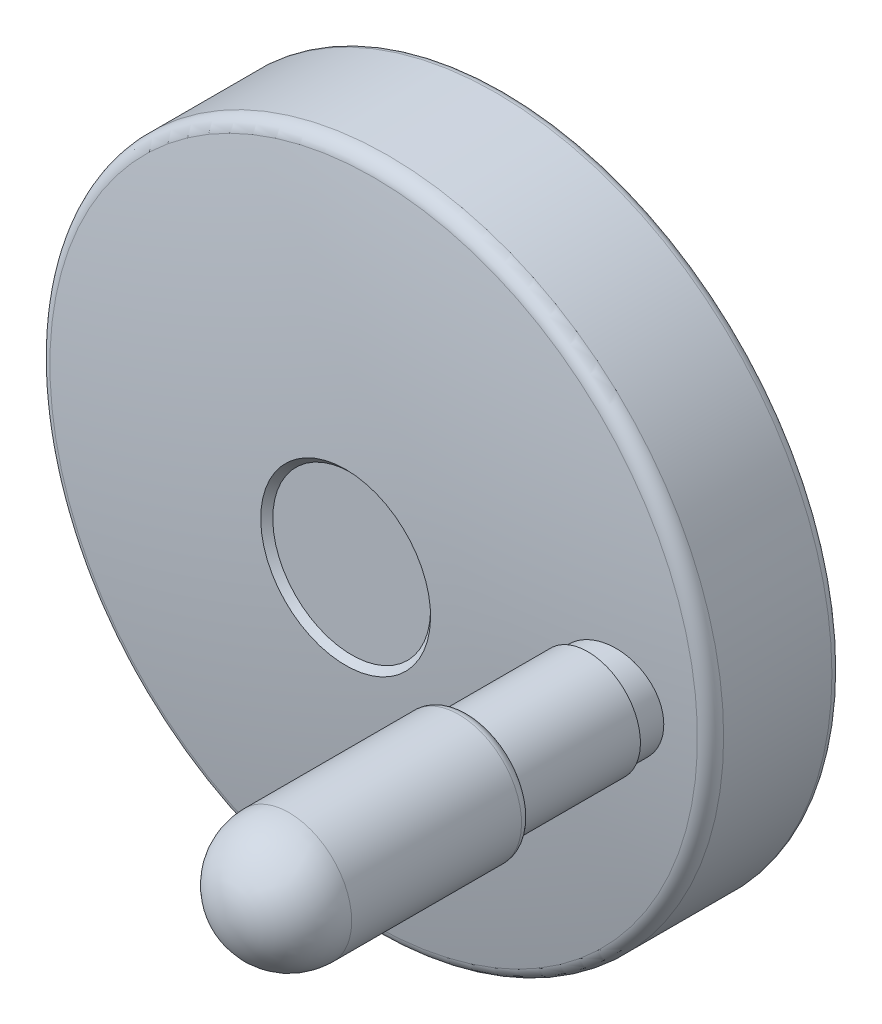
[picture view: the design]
ISO-10303-21;
HEADER;
FILE_DESCRIPTION(('STEP AP214'),'2;1');
FILE_NAME('part.step','',(''),(''),'','','');
FILE_SCHEMA(('AUTOMOTIVE_DESIGN { 1 0 10303 214 1 1 1 1 }'));
ENDSEC;
DATA;
#1=APPLICATION_CONTEXT('core data for automotive mechanical design processes');
#2=APPLICATION_PROTOCOL_DEFINITION('international standard','automotive_design',2000,#1);
#3=PRODUCT_CONTEXT('',#1,'mechanical');
#4=PRODUCT('Part','Part','',(#3));
#5=PRODUCT_RELATED_PRODUCT_CATEGORY('part','',(#4));
#6=PRODUCT_DEFINITION_FORMATION('','',#4);
#7=PRODUCT_DEFINITION_CONTEXT('part definition',#1,'design');
#8=PRODUCT_DEFINITION('design','',#6,#7);
#9=PRODUCT_DEFINITION_SHAPE('','',#8);
#10=(LENGTH_UNIT() NAMED_UNIT(*) SI_UNIT(.MILLI.,.METRE.));
#11=(NAMED_UNIT(*) PLANE_ANGLE_UNIT() SI_UNIT($,.RADIAN.));
#12=(NAMED_UNIT(*) SI_UNIT($,.STERADIAN.) SOLID_ANGLE_UNIT());
#13=UNCERTAINTY_MEASURE_WITH_UNIT(LENGTH_MEASURE(1.E-05),#10,'distance_accuracy_value','');
#14=(GEOMETRIC_REPRESENTATION_CONTEXT(3) GLOBAL_UNCERTAINTY_ASSIGNED_CONTEXT((#13)) GLOBAL_UNIT_ASSIGNED_CONTEXT((#10,
#11,#12)) REPRESENTATION_CONTEXT('',''));
#15=CARTESIAN_POINT('',(0.,0.,0.));
#16=DIRECTION('',(0.,0.,1.));
#17=DIRECTION('',(1.,0.,0.));
#18=AXIS2_PLACEMENT_3D('',#15,#16,#17);
#19=CARTESIAN_POINT('',(0.,0.,29.));
#20=DIRECTION('',(0.,0.,1.));
#21=DIRECTION('',(0.,1.,0.));
#22=AXIS2_PLACEMENT_3D('',#19,#20,#21);
#23=PLANE('',#22);
#24=CARTESIAN_POINT('',(30.5,0.,29.));
#25=DIRECTION('',(0.,0.,1.));
#26=DIRECTION('',(0.,1.,0.));
#27=AXIS2_PLACEMENT_3D('',#24,#25,#26);
#28=CIRCLE('',#27,4.875);
#29=CARTESIAN_POINT('',(30.5,4.87499999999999,29.));
#30=VERTEX_POINT('',#29);
#31=EDGE_CURVE('E297',#30,#30,#28,.T.);
#32=ORIENTED_EDGE('',*,*,#31,.F.);
#33=EDGE_LOOP('',(#32));
#34=FACE_BOUND('',#33,.T.);
#35=CARTESIAN_POINT('',(30.5,0.,29.));
#36=DIRECTION('',(0.,0.,-1.));
#37=DIRECTION('',(0.,-1.,0.));
#38=AXIS2_PLACEMENT_3D('',#35,#36,#37);
#39=CIRCLE('',#38,6.);
#40=CARTESIAN_POINT('',(30.5,-6.,29.));
#41=VERTEX_POINT('',#40);
#42=EDGE_CURVE('E768',#41,#41,#39,.T.);
#43=ORIENTED_EDGE('',*,*,#42,.F.);
#44=EDGE_LOOP('',(#43));
#45=FACE_BOUND('',#44,.T.);
#46=ADVANCED_FACE('F15',(#34,#45),#23,.T.);
#47=CARTESIAN_POINT('',(30.5,0.,25.));
#48=DIRECTION('',(0.,0.,-1.));
#49=DIRECTION('',(0.,-1.,0.));
#50=AXIS2_PLACEMENT_3D('',#47,#48,#49);
#51=CYLINDRICAL_SURFACE('',#50,6.);
#52=CARTESIAN_POINT('',(24.5,0.,27.6143071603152));
#53=CARTESIAN_POINT('',(24.5000009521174,0.167229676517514,27.6143070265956));
#54=CARTESIAN_POINT('',(24.5069975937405,0.334490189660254,27.6133186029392));
#55=CARTESIAN_POINT('',(24.5349379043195,0.66785375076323,27.6093713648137));
#56=CARTESIAN_POINT('',(24.5558858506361,0.833956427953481,27.606411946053));
#57=CARTESIAN_POINT('',(24.6116186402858,1.16405510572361,27.5985380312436));
#58=CARTESIAN_POINT('',(24.6464255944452,1.3280473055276,27.5936204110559));
#59=CARTESIAN_POINT('',(24.7296467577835,1.65260800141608,27.5818621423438));
#60=CARTESIAN_POINT('',(24.7780716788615,1.81317369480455,27.5750199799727));
#61=CARTESIAN_POINT('',(24.8880461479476,2.12930204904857,27.5594802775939));
#62=CARTESIAN_POINT('',(24.9495700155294,2.28487382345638,27.5507863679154));
#63=CARTESIAN_POINT('',(25.0853707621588,2.59031604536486,27.5315950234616));
#64=CARTESIAN_POINT('',(25.1596533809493,2.74018388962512,27.5210967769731));
#65=CARTESIAN_POINT('',(25.3204096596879,3.0331103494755,27.4983754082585));
#66=CARTESIAN_POINT('',(25.4068843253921,3.17616840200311,27.4861521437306));
#67=CARTESIAN_POINT('',(25.591344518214,3.45441028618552,27.4600760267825));
#68=CARTESIAN_POINT('',(25.6893249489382,3.58959756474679,27.4462238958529));
#69=CARTESIAN_POINT('',(25.8966280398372,3.85188881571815,27.4169129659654));
#70=CARTESIAN_POINT('',(26.0060044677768,3.97894944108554,27.4014465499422));
#71=CARTESIAN_POINT('',(26.2347880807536,4.22326275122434,27.3690915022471));
#72=CARTESIAN_POINT('',(26.3541854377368,4.34052482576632,27.3522042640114));
#73=CARTESIAN_POINT('',(26.6023049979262,4.56463962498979,27.3171064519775));
#74=CARTESIAN_POINT('',(26.7310317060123,4.67148726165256,27.2988952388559));
#75=CARTESIAN_POINT('',(26.9968731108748,4.87401595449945,27.2612810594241));
#76=CARTESIAN_POINT('',(27.1339898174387,4.96969431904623,27.2418778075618));
#77=CARTESIAN_POINT('',(27.4168805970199,5.15002553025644,27.2018404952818));
#78=CARTESIAN_POINT('',(27.5627213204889,5.2345717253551,27.1811969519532));
#79=CARTESIAN_POINT('',(27.8609443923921,5.39108100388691,27.1389775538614));
#80=CARTESIAN_POINT('',(28.0133291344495,5.46303943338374,27.1174013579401));
#81=CARTESIAN_POINT('',(28.3234609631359,5.59383505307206,27.0734828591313));
#82=CARTESIAN_POINT('',(28.4812062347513,5.65267663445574,27.051140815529));
#83=CARTESIAN_POINT('',(28.8010597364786,5.75690064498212,27.0058315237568));
#84=CARTESIAN_POINT('',(28.9631695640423,5.80227807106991,26.9828640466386));
#85=CARTESIAN_POINT('',(29.291955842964,5.8795739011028,26.9362744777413));
#86=CARTESIAN_POINT('',(29.4586593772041,5.91137478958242,26.9126484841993));
#87=CARTESIAN_POINT('',(29.7941802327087,5.96075351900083,26.865088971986));
#88=CARTESIAN_POINT('',(29.9629983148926,5.97832608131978,26.8411553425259));
#89=CARTESIAN_POINT('',(30.3014406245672,5.99910895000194,26.7931657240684));
#90=CARTESIAN_POINT('',(30.4710645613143,6.002324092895,26.7691097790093));
#91=CARTESIAN_POINT('',(30.8100436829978,5.9943828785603,26.7210279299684));
#92=CARTESIAN_POINT('',(30.9793987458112,5.98322122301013,26.6970020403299));
#93=CARTESIAN_POINT('',(31.3172944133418,5.94651420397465,26.6490578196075));
#94=CARTESIAN_POINT('',(31.4858285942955,5.92090852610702,26.6251403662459));
#95=CARTESIAN_POINT('',(31.8202181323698,5.8554299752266,26.5776778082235));
#96=CARTESIAN_POINT('',(31.9860725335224,5.8155521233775,26.5541328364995));
#97=CARTESIAN_POINT('',(32.3138307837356,5.72180624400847,26.5075962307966));
#98=CARTESIAN_POINT('',(32.4757352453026,5.66794040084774,26.4846045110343));
#99=CARTESIAN_POINT('',(32.7944560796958,5.54657992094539,26.4393365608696));
#100=CARTESIAN_POINT('',(32.9512724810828,5.47908536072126,26.4170603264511));
#101=CARTESIAN_POINT('',(33.2584436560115,5.33104219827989,26.3734192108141));
#102=CARTESIAN_POINT('',(33.4088081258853,5.25051411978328,26.3520529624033));
#103=CARTESIAN_POINT('',(33.7021894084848,5.07691097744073,26.3103586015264));
#104=CARTESIAN_POINT('',(33.8452088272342,4.98384040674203,26.2900301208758));
#105=CARTESIAN_POINT('',(34.1229453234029,4.7857464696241,26.2505479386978));
#106=CARTESIAN_POINT('',(34.2576602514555,4.680720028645,26.2313945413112));
#107=CARTESIAN_POINT('',(34.5177008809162,4.45950749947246,26.1944180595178));
#108=CARTESIAN_POINT('',(34.6430301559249,4.34332569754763,26.176594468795));
#109=CARTESIAN_POINT('',(34.8825480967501,4.10146660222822,26.1425277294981));
#110=CARTESIAN_POINT('',(34.9968109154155,3.97586422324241,26.1262740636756));
#111=CARTESIAN_POINT('',(35.2143248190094,3.71536314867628,26.0953299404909));
#112=CARTESIAN_POINT('',(35.3175801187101,3.58046804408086,26.0806388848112));
#113=CARTESIAN_POINT('',(35.5124335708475,3.3021790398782,26.0529128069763));
#114=CARTESIAN_POINT('',(35.6040221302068,3.15877828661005,26.0398791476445));
#115=CARTESIAN_POINT('',(35.7747155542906,2.86465960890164,26.0155864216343));
#116=CARTESIAN_POINT('',(35.8538252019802,2.71394451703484,26.004326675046));
#117=CARTESIAN_POINT('',(35.998374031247,2.40755662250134,25.9837515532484));
#118=CARTESIAN_POINT('',(36.0639247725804,2.25193750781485,25.9744203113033));
#119=CARTESIAN_POINT('',(36.18168352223,1.93569835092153,25.957656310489));
#120=CARTESIAN_POINT('',(36.2338967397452,1.77508028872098,25.9502228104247));
#121=CARTESIAN_POINT('',(36.3245353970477,1.45023312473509,25.9373182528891));
#122=CARTESIAN_POINT('',(36.3629849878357,1.28601089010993,25.9318437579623));
#123=CARTESIAN_POINT('',(36.4259166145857,0.954926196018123,25.9228832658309));
#124=CARTESIAN_POINT('',(36.4504056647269,0.788065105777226,25.9193962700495));
#125=CARTESIAN_POINT('',(36.4785444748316,0.517442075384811,25.9153895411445));
#126=CARTESIAN_POINT('',(36.4865876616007,0.414126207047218,25.9142442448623));
#127=CARTESIAN_POINT('',(36.4973157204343,0.207210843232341,25.9127166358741));
#128=CARTESIAN_POINT('',(36.5000005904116,0.103611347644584,25.9123343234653));
#129=CARTESIAN_POINT('',(36.4999990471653,-0.167212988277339,25.9123345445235));
#130=CARTESIAN_POINT('',(36.4930037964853,-0.334456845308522,25.9133306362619));
#131=CARTESIAN_POINT('',(36.4650690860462,-0.667787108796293,25.9173083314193));
#132=CARTESIAN_POINT('',(36.4441253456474,-0.833873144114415,25.9202905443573));
#133=CARTESIAN_POINT('',(36.3884038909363,-1.16393864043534,25.9282245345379));
#134=CARTESIAN_POINT('',(36.3536040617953,-1.32791429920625,25.933179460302));
#135=CARTESIAN_POINT('',(36.2704002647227,-1.65244196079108,25.9450257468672));
#136=CARTESIAN_POINT('',(36.221985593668,-1.81299116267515,25.9519186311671));
#137=CARTESIAN_POINT('',(36.1120351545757,-2.12908618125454,25.9675715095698));
#138=CARTESIAN_POINT('',(36.0505251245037,-2.28464113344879,25.9763278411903));
#139=CARTESIAN_POINT('',(35.9147556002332,-2.59005051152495,25.9956540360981));
#140=CARTESIAN_POINT('',(35.8404903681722,-2.73990233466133,26.0062247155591));
#141=CARTESIAN_POINT('',(35.6797723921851,-3.03279819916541,26.0290988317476));
#142=CARTESIAN_POINT('',(35.5933186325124,-3.17584167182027,26.0414024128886));
#143=CARTESIAN_POINT('',(35.4089037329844,-3.45405634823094,26.0676446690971));
#144=CARTESIAN_POINT('',(35.3109476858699,-3.58923099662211,26.0815826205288));
#145=CARTESIAN_POINT('',(35.1036876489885,-3.85151105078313,26.111069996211));
#146=CARTESIAN_POINT('',(34.9943289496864,-3.97857235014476,26.1266271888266));
#147=CARTESIAN_POINT('',(34.7655819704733,-4.22288853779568,26.159164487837));
#148=CARTESIAN_POINT('',(34.6462035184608,-4.34015281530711,26.1761431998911));
#149=CARTESIAN_POINT('',(34.398122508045,-4.56427410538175,26.211422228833));
#150=CARTESIAN_POINT('',(34.2694154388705,-4.67112602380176,26.2297231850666));
#151=CARTESIAN_POINT('',(34.0036135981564,-4.87366567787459,26.2675125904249));
#152=CARTESIAN_POINT('',(33.8665168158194,-4.96935072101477,26.2870013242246));
#153=CARTESIAN_POINT('',(33.5836468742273,-5.14971003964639,26.3272063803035));
#154=CARTESIAN_POINT('',(33.4378060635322,-5.23427609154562,26.3479322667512));
#155=CARTESIAN_POINT('',(33.1395801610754,-5.39082451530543,26.3903076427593));
#156=CARTESIAN_POINT('',(32.9871926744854,-5.46280223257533,26.4119574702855));
#157=CARTESIAN_POINT('',(32.6770523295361,-5.59363564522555,26.4560124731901));
#158=CARTESIAN_POINT('',(32.5193012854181,-5.65249572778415,26.4784173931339));
#159=CARTESIAN_POINT('',(32.1994329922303,-5.75675557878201,26.5238400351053));
#160=CARTESIAN_POINT('',(32.037314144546,-5.80215034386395,26.546857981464));
#161=CARTESIAN_POINT('',(31.7085023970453,-5.87948025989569,26.5935356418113));
#162=CARTESIAN_POINT('',(31.5417823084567,-5.91129754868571,26.6171991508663));
#163=CARTESIAN_POINT('',(31.2062247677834,-5.96070612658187,26.6648187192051));
#164=CARTESIAN_POINT('',(31.0373865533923,-5.97829213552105,26.6887748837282));
#165=CARTESIAN_POINT('',(30.6989007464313,-5.99909827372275,26.7367939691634));
#166=CARTESIAN_POINT('',(30.5292534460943,-6.00232324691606,26.7608568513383));
#167=CARTESIAN_POINT('',(30.1902247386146,-5.99439745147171,26.8089368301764));
#168=CARTESIAN_POINT('',(30.0208434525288,-5.98324138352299,26.832953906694));
#169=CARTESIAN_POINT('',(29.6829113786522,-5.94654272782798,26.8808623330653));
#170=CARTESIAN_POINT('',(29.5143668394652,-5.92094136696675,26.9047527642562));
#171=CARTESIAN_POINT('',(29.1799545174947,-5.85546920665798,26.9521464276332));
#172=CARTESIAN_POINT('',(29.0140876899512,-5.81559342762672,26.9756495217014));
#173=CARTESIAN_POINT('',(28.6863032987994,-5.72184911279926,27.0220886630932));
#174=CARTESIAN_POINT('',(28.5243851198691,-5.66798277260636,27.0450247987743));
#175=CARTESIAN_POINT('',(28.2056361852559,-5.54661851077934,27.0901694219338));
#176=CARTESIAN_POINT('',(28.0488054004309,-5.47912066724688,27.1123779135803));
#177=CARTESIAN_POINT('',(27.7416272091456,-5.33107857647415,27.1558703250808));
#178=CARTESIAN_POINT('',(27.5912692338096,-5.25055670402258,27.1771557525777));
#179=CARTESIAN_POINT('',(27.2978996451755,-5.07696686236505,27.2186807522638));
#180=CARTESIAN_POINT('',(27.1548854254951,-4.98390338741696,27.2389206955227));
#181=CARTESIAN_POINT('',(26.877158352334,-4.78582465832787,27.2782205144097));
#182=CARTESIAN_POINT('',(26.7424476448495,-4.68080633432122,27.297280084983));
#183=CARTESIAN_POINT('',(26.4824145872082,-4.45961119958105,27.3340663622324));
#184=CARTESIAN_POINT('',(26.3570886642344,-4.343438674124,27.3517935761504));
#185=CARTESIAN_POINT('',(26.1175812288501,-4.10160413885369,27.3856677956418));
#186=CARTESIAN_POINT('',(26.0033251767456,-3.97601742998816,27.4018253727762));
#187=CARTESIAN_POINT('',(25.7858230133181,-3.71554996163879,27.4325804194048));
#188=CARTESIAN_POINT('',(25.6825726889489,-3.58067279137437,27.4471784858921));
#189=CARTESIAN_POINT('',(25.4877270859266,-3.30242197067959,27.4747242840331));
#190=CARTESIAN_POINT('',(25.3961414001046,-3.1590414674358,27.4876706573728));
#191=CARTESIAN_POINT('',(25.2254511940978,-2.86496548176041,27.5117972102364));
#192=CARTESIAN_POINT('',(25.1463418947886,-2.71427282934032,27.5229780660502));
#193=CARTESIAN_POINT('',(25.001783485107,-2.40791608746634,27.5434077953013));
#194=CARTESIAN_POINT('',(24.9362241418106,-2.25230504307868,27.5526722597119));
#195=CARTESIAN_POINT('',(24.8184475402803,-1.93608259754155,27.569314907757));
#196=CARTESIAN_POINT('',(24.7662250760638,-1.77547317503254,27.576693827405));
#197=CARTESIAN_POINT('',(24.675566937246,-1.45064340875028,27.5895031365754));
#198=CARTESIAN_POINT('',(24.6371071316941,-1.28642992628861,27.5949369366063));
#199=CARTESIAN_POINT('',(24.5741539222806,-0.955362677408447,27.6038310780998));
#200=CARTESIAN_POINT('',(24.5496535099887,-0.788510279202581,27.6072924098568));
#201=CARTESIAN_POINT('',(24.5214869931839,-0.517820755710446,27.6112716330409));
#202=CARTESIAN_POINT('',(24.5134320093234,-0.414429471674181,27.6124095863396));
#203=CARTESIAN_POINT('',(24.5026882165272,-0.207362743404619,27.6139273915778));
#204=CARTESIAN_POINT('',(24.4999994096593,-0.103687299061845,27.6143072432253));
#205=CARTESIAN_POINT('',(24.5,0.,27.6143071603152));
#206=B_SPLINE_CURVE_WITH_KNOTS('',3,(#52,#53,#54,#55,#56,#57,#58,#59,#60,#61,#62,#63,#64,#65,
#66,#67,#68,#69,#70,#71,#72,#73,#74,#75,#76,#77,#78,#79,#80,#81,#82,#83,#84,#85,#86,#87,#88,#89,
#90,#91,#92,#93,#94,#95,#96,#97,#98,#99,#100,#101,#102,#103,#104,#105,#106,#107,#108,#109,#110,
#111,#112,#113,#114,#115,#116,#117,#118,#119,#120,#121,#122,#123,#124,#125,#126,#127,#128,#129,
#130,#131,#132,#133,#134,#135,#136,#137,#138,#139,#140,#141,#142,#143,#144,#145,#146,#147,#148,
#149,#150,#151,#152,#153,#154,#155,#156,#157,#158,#159,#160,#161,#162,#163,#164,#165,#166,#167,
#168,#169,#170,#171,#172,#173,#174,#175,#176,#177,#178,#179,#180,#181,#182,#183,#184,#185,#186,
#187,#188,#189,#190,#191,#192,#193,#194,#195,#196,#197,#198,#199,#200,#201,#202,#203,#204,#205),
.UNSPECIFIED.,.T.,.F.,(4,2,2,2,2,2,2,2,2,2,2,2,2,2,2,2,2,2,2,2,2,2,2,2,2,2,2,2,2,2,2,2,2,2,2,2,
2,2,2,2,2,2,2,2,2,2,2,2,2,2,2,2,2,2,2,2,2,2,2,2,2,2,2,2,2,2,2,2,2,2,2,2,2,2,2,2,4),(0.,
0.501593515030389,1.00334088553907,1.50589197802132,2.00883948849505,2.51080990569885,
3.0130067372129,3.51524502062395,4.01726167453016,4.52176449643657,5.02577818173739,
5.5300368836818,6.03441685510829,6.54332326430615,7.05241743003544,7.56134090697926,
8.07045325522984,8.58388716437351,9.09751146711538,9.61096273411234,10.1246032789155,
10.6404046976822,11.1563862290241,11.6722872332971,12.18818534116,12.7032788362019,
13.21818829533,13.733230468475,14.2480755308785,14.7591895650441,15.2701071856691,
15.7814422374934,16.2925808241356,16.7993300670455,17.3058810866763,17.8115388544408,
18.3169423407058,18.6277171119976,18.938492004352,19.4400355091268,19.94173300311,
20.4442344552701,20.9471320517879,21.4490502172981,21.9511947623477,22.4533811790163,
22.9553460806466,23.4598410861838,23.9638469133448,24.4680980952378,24.9724706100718,
25.4814369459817,25.9905910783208,26.4995746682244,27.0087471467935,27.5222538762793,
28.0359510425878,28.5494749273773,29.063188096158,29.5790066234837,30.0950052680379,
30.6109229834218,31.1268377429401,31.6418754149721,32.1567290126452,32.6717151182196,
33.1865041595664,33.6975427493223,34.2083850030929,34.7196446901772,35.2307080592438,
35.7374341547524,36.2439621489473,36.7495976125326,37.2549789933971,37.5659815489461,
37.8769842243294),.UNSPECIFIED.);
#207=CARTESIAN_POINT('',(24.5,0.,27.6143071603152));
#208=VERTEX_POINT('',#207);
#209=EDGE_CURVE('E762',#208,#208,#206,.T.);
#210=ORIENTED_EDGE('',*,*,#209,.F.);
#211=EDGE_LOOP('',(#210));
#212=FACE_BOUND('',#211,.T.);
#213=ORIENTED_EDGE('',*,*,#42,.T.);
#214=EDGE_LOOP('',(#213));
#215=FACE_BOUND('',#214,.T.);
#216=ADVANCED_FACE('F530',(#212,#215),#51,.T.);
#217=CARTESIAN_POINT('',(0.,0.,-188.281250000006));
#218=DIRECTION('',(-1.,0.,0.));
#219=DIRECTION('',(0.,0.,1.));
#220=AXIS2_PLACEMENT_3D('',#217,#218,#219);
#221=SPHERICAL_SURFACE('',#220,217.281250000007);
#222=CARTESIAN_POINT('',(0.,0.,25.2804746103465));
#223=DIRECTION('',(0.,0.,1.));
#224=DIRECTION('',(0.,1.,0.));
#225=AXIS2_PLACEMENT_3D('',#222,#223,#224);
#226=CIRCLE('',#225,40.0316297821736);
#227=CARTESIAN_POINT('',(0.,40.0316297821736,25.2804746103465));
#228=VERTEX_POINT('',#227);
#229=EDGE_CURVE('E291',#228,#228,#226,.T.);
#230=ORIENTED_EDGE('',*,*,#229,.T.);
#231=EDGE_LOOP('',(#230));
#232=FACE_BOUND('',#231,.T.);
#233=CARTESIAN_POINT('',(0.,0.,28.7461482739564));
#234=DIRECTION('',(0.,0.,1.));
#235=DIRECTION('',(0.,1.,0.));
#236=AXIS2_PLACEMENT_3D('',#233,#234,#235);
#237=CIRCLE('',#236,10.5);
#238=CARTESIAN_POINT('',(0.,10.5,28.7461482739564));
#239=VERTEX_POINT('',#238);
#240=EDGE_CURVE('E766',#239,#239,#237,.F.);
#241=ORIENTED_EDGE('',*,*,#240,.T.);
#242=EDGE_LOOP('',(#241));
#243=FACE_BOUND('',#242,.T.);
#244=ORIENTED_EDGE('',*,*,#209,.T.);
#245=EDGE_LOOP('',(#244));
#246=FACE_BOUND('',#245,.T.);
#247=ADVANCED_FACE('F510',(#232,#243,#246),#221,.T.);
#248=CARTESIAN_POINT('',(0.,0.,23.5112878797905));
#249=DIRECTION('',(0.,0.,1.));
#250=DIRECTION('',(0.,1.,0.));
#251=AXIS2_PLACEMENT_3D('',#248,#249,#250);
#252=TOROIDAL_SURFACE('',#251,39.7,1.8);
#253=CARTESIAN_POINT('',(0.,0.,23.5112878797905));
#254=DIRECTION('',(0.,0.,1.));
#255=DIRECTION('',(0.,1.,0.));
#256=AXIS2_PLACEMENT_3D('',#253,#254,#255);
#257=CIRCLE('',#256,41.5);
#258=CARTESIAN_POINT('',(0.,41.5,23.5112878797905));
#259=VERTEX_POINT('',#258);
#260=EDGE_CURVE('E760',#259,#259,#257,.T.);
#261=ORIENTED_EDGE('',*,*,#260,.T.);
#262=EDGE_LOOP('',(#261));
#263=FACE_BOUND('',#262,.T.);
#264=ORIENTED_EDGE('',*,*,#229,.F.);
#265=EDGE_LOOP('',(#264));
#266=FACE_BOUND('',#265,.T.);
#267=ADVANCED_FACE('F504',(#263,#266),#252,.T.);
#268=CARTESIAN_POINT('',(0.,0.,28.7461482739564));
#269=DIRECTION('',(0.,0.,1.));
#270=DIRECTION('',(0.,1.,0.));
#271=AXIS2_PLACEMENT_3D('',#268,#269,#270);
#272=CONICAL_SURFACE('',#271,10.5,0.785398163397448);
#273=CARTESIAN_POINT('',(0.,0.,28.));
#274=DIRECTION('',(0.,0.,1.));
#275=DIRECTION('',(0.,1.,0.));
#276=AXIS2_PLACEMENT_3D('',#273,#274,#275);
#277=CIRCLE('',#276,9.75385172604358);
#278=CARTESIAN_POINT('',(0.,9.75385172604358,28.));
#279=VERTEX_POINT('',#278);
#280=EDGE_CURVE('E763',#279,#279,#277,.T.);
#281=ORIENTED_EDGE('',*,*,#280,.F.);
#282=EDGE_LOOP('',(#281));
#283=FACE_BOUND('',#282,.T.);
#284=ORIENTED_EDGE('',*,*,#240,.F.);
#285=EDGE_LOOP('',(#284));
#286=FACE_BOUND('',#285,.T.);
#287=ADVANCED_FACE('F509',(#283,#286),#272,.F.);
#288=CARTESIAN_POINT('',(0.,0.,16.8181439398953));
#289=DIRECTION('',(0.,0.,-1.));
#290=DIRECTION('',(0.,-1.,0.));
#291=AXIS2_PLACEMENT_3D('',#288,#289,#290);
#292=CYLINDRICAL_SURFACE('',#291,41.5);
#293=CARTESIAN_POINT('',(0.,0.,10.125));
#294=DIRECTION('',(0.,0.,-1.));
#295=DIRECTION('',(0.,-1.,0.));
#296=AXIS2_PLACEMENT_3D('',#293,#294,#295);
#297=CIRCLE('',#296,41.5);
#298=CARTESIAN_POINT('',(0.,-41.5,10.125));
#299=VERTEX_POINT('',#298);
#300=EDGE_CURVE('E648',#299,#299,#297,.F.);
#301=ORIENTED_EDGE('',*,*,#300,.T.);
#302=EDGE_LOOP('',(#301));
#303=FACE_BOUND('',#302,.T.);
#304=ORIENTED_EDGE('',*,*,#260,.F.);
#305=EDGE_LOOP('',(#304));
#306=FACE_BOUND('',#305,.T.);
#307=ADVANCED_FACE('F522',(#303,#306),#292,.T.);
#308=CARTESIAN_POINT('',(-4.87692586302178,0.,28.));
#309=DIRECTION('',(0.,0.,1.));
#310=DIRECTION('',(0.,1.,0.));
#311=AXIS2_PLACEMENT_3D('',#308,#309,#310);
#312=PLANE('',#311);
#313=ORIENTED_EDGE('',*,*,#280,.T.);
#314=EDGE_LOOP('',(#313));
#315=FACE_BOUND('',#314,.T.);
#316=ADVANCED_FACE('F637',(#315),#312,.T.);
#317=CARTESIAN_POINT('',(0.,0.,10.125));
#318=DIRECTION('',(0.,0.,1.));
#319=DIRECTION('',(0.,1.,0.));
#320=AXIS2_PLACEMENT_3D('',#317,#318,#319);
#321=TOROIDAL_SURFACE('',#320,40.375,1.125);
#322=ORIENTED_EDGE('',*,*,#300,.F.);
#323=EDGE_LOOP('',(#322));
#324=FACE_BOUND('',#323,.T.);
#325=CARTESIAN_POINT('',(0.,0.,9.));
#326=DIRECTION('',(0.,0.,1.));
#327=DIRECTION('',(0.,-1.,0.));
#328=AXIS2_PLACEMENT_3D('',#325,#326,#327);
#329=CIRCLE('',#328,40.375);
#330=CARTESIAN_POINT('',(0.,-40.375,8.9999999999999));
#331=VERTEX_POINT('',#330);
#332=CARTESIAN_POINT('',(0.,40.375,8.9999999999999));
#333=VERTEX_POINT('',#332);
#334=EDGE_CURVE('E677',#331,#333,#329,.T.);
#335=ORIENTED_EDGE('',*,*,#334,.T.);
#336=CARTESIAN_POINT('',(0.,0.,9.));
#337=DIRECTION('',(0.,0.,1.));
#338=DIRECTION('',(0.,1.,0.));
#339=AXIS2_PLACEMENT_3D('',#336,#337,#338);
#340=CIRCLE('',#339,40.375);
#341=CARTESIAN_POINT('',(-40.375,0.,9.));
#342=VERTEX_POINT('',#341);
#343=EDGE_CURVE('E619',#333,#342,#340,.T.);
#344=ORIENTED_EDGE('',*,*,#343,.T.);
#345=CARTESIAN_POINT('',(0.,0.,9.));
#346=DIRECTION('',(0.,0.,1.));
#347=DIRECTION('',(-1.,0.,0.));
#348=AXIS2_PLACEMENT_3D('',#345,#346,#347);
#349=CIRCLE('',#348,40.375);
#350=EDGE_CURVE('E653',#342,#331,#349,.T.);
#351=ORIENTED_EDGE('',*,*,#350,.T.);
#352=EDGE_LOOP('',(#335,#344,#351));
#353=FACE_BOUND('',#352,.T.);
#354=ADVANCED_FACE('F625',(#324,#353),#321,.T.);
#355=CARTESIAN_POINT('',(-40.1075,0.,9.));
#356=DIRECTION('',(0.,0.,-1.));
#357=DIRECTION('',(-1.,0.,0.));
#358=AXIS2_PLACEMENT_3D('',#355,#356,#357);
#359=PLANE('',#358);
#360=CARTESIAN_POINT('',(0.,0.,9.));
#361=DIRECTION('',(0.,0.,-1.));
#362=DIRECTION('',(0.,-1.,0.));
#363=AXIS2_PLACEMENT_3D('',#360,#361,#362);
#364=CIRCLE('',#363,39.84);
#365=CARTESIAN_POINT('',(0.,-39.84,9.));
#366=VERTEX_POINT('',#365);
#367=EDGE_CURVE('E697',#366,#366,#364,.F.);
#368=ORIENTED_EDGE('',*,*,#367,.T.);
#369=EDGE_LOOP('',(#368));
#370=FACE_BOUND('',#369,.T.);
#371=ORIENTED_EDGE('',*,*,#343,.F.);
#372=ORIENTED_EDGE('',*,*,#334,.F.);
#373=ORIENTED_EDGE('',*,*,#350,.F.);
#374=EDGE_LOOP('',(#371,#372,#373));
#375=FACE_BOUND('',#374,.T.);
#376=ADVANCED_FACE('F636',(#370,#375),#359,.T.);
#377=CARTESIAN_POINT('',(0.,0.,16.2811848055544));
#378=DIRECTION('',(0.,0.,-1.));
#379=DIRECTION('',(0.,-1.,0.));
#380=AXIS2_PLACEMENT_3D('',#377,#378,#379);
#381=CYLINDRICAL_SURFACE('',#380,28.22);
#382=CARTESIAN_POINT('',(27.819430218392,-4.7379006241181,19.0571345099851));
#383=CARTESIAN_POINT('',(27.8371846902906,-4.63364547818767,18.957664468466));
#384=CARTESIAN_POINT('',(27.8544001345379,-4.52902740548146,18.8584762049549));
#385=CARTESIAN_POINT('',(27.8877496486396,-4.31892928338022,18.6608183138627));
#386=CARTESIAN_POINT('',(27.9038836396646,-4.21344917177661,18.5623487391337));
#387=CARTESIAN_POINT('',(27.9351126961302,-4.0011773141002,18.3659938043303));
#388=CARTESIAN_POINT('',(27.9502043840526,-3.89438251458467,18.2681112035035));
#389=CARTESIAN_POINT('',(27.9792868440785,-3.67962639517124,18.0734743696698));
#390=CARTESIAN_POINT('',(27.9932776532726,-3.57166511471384,17.9767200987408));
#391=CARTESIAN_POINT('',(28.021263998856,-3.34532891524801,17.776684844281));
#392=CARTESIAN_POINT('',(28.0351638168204,-3.22683252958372,17.6735275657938));
#393=CARTESIAN_POINT('',(28.0616466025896,-2.98778417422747,17.4694517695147));
#394=CARTESIAN_POINT('',(28.0742296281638,-2.86723229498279,17.368533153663));
#395=CARTESIAN_POINT('',(28.0980393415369,-2.62365095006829,17.1698816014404));
#396=CARTESIAN_POINT('',(28.1092677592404,-2.50062488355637,17.0721447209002));
#397=CARTESIAN_POINT('',(28.1303452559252,-2.25116719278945,16.8809843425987));
#398=CARTESIAN_POINT('',(28.1401946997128,-2.12473647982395,16.7875597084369));
#399=CARTESIAN_POINT('',(28.1559846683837,-1.90204985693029,16.6313949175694));
#400=CARTESIAN_POINT('',(28.1622627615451,-1.80685855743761,16.567178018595));
#401=CARTESIAN_POINT('',(28.1740071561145,-1.61341801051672,16.4433045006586));
#402=CARTESIAN_POINT('',(28.1794731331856,-1.51516756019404,16.3836497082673));
#403=CARTESIAN_POINT('',(28.1894189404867,-1.31707723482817,16.2718646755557));
#404=CARTESIAN_POINT('',(28.1939168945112,-1.2173127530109,16.2196038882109));
#405=CARTESIAN_POINT('',(28.2019702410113,-1.01372159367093,16.1235831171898));
#406=CARTESIAN_POINT('',(28.2055264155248,-0.909898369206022,16.0798160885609));
#407=CARTESIAN_POINT('',(28.2102855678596,-0.7429106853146,16.0200461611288));
#408=CARTESIAN_POINT('',(28.2118472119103,-0.681155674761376,16.0001363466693));
#409=CARTESIAN_POINT('',(28.2145840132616,-0.556365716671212,15.9649002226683));
#410=CARTESIAN_POINT('',(28.2157594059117,-0.493331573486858,15.9495711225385));
#411=CARTESIAN_POINT('',(28.2177136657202,-0.364991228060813,15.9239206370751));
#412=CARTESIAN_POINT('',(28.2184846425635,-0.299664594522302,15.9136990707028));
#413=CARTESIAN_POINT('',(28.2195760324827,-0.168210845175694,15.8991702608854));
#414=CARTESIAN_POINT('',(28.2198954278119,-0.102082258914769,15.8948763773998));
#415=CARTESIAN_POINT('',(28.219977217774,-0.0358584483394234,15.8938047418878));
#416=B_SPLINE_CURVE_WITH_KNOTS('',3,(#382,#383,#384,#385,#386,#387,#388,#389,#390,#391,#392,
#393,#394,#395,#396,#397,#398,#399,#400,#401,#402,#403,#404,#405,#406,#407,#408,#409,#410,#411,
#412,#413,#414,#415),.UNSPECIFIED.,.F.,.F.,(4,2,2,2,2,2,2,2,2,2,2,2,2,2,2,2,4),(0.,
0.435555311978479,0.871142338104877,1.30808037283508,1.74500367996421,2.21814032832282,
2.69125621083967,3.16376135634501,3.63614126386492,3.9810405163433,4.32607714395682,
4.66394758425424,5.00153657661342,5.19610304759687,5.39055074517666,5.58866297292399,
5.78722098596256),.UNSPECIFIED.);
#417=CARTESIAN_POINT('',(28.2061340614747,-0.884534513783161,16.0720000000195));
#418=VERTEX_POINT('',#417);
#419=CARTESIAN_POINT('',(28.1576786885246,-1.87444148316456,16.6135));
#420=VERTEX_POINT('',#419);
#421=EDGE_CURVE('E9',#418,#420,#416,.F.);
#422=ORIENTED_EDGE('',*,*,#421,.F.);
#423=DIRECTION('',(0.,0.,1.));
#424=VECTOR('',#423,1.);
#425=CARTESIAN_POINT('',(28.2061340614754,-0.884534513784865,21.75));
#426=LINE('',#425,#424);
#427=CARTESIAN_POINT('',(28.2061340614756,-0.884534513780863,15.0415000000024));
#428=VERTEX_POINT('',#427);
#429=EDGE_CURVE('E702',#418,#428,#426,.F.);
#430=ORIENTED_EDGE('',*,*,#429,.T.);
#431=CARTESIAN_POINT('',(28.2061340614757,-0.884534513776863,15.0415000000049));
#432=CARTESIAN_POINT('',(28.2033697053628,-0.972611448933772,15.0071759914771));
#433=CARTESIAN_POINT('',(28.200246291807,-1.05911764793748,14.9691713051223));
#434=CARTESIAN_POINT('',(28.1933520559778,-1.22903996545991,14.8874249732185));
#435=CARTESIAN_POINT('',(28.1895832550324,-1.31246477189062,14.8437013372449));
#436=CARTESIAN_POINT('',(28.1814548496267,-1.47673995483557,14.7519530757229));
#437=CARTESIAN_POINT('',(28.1770957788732,-1.55759257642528,14.7039323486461));
#438=CARTESIAN_POINT('',(28.1678059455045,-1.71741116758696,14.6043552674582));
#439=CARTESIAN_POINT('',(28.1628734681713,-1.79637058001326,14.5527885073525));
#440=CARTESIAN_POINT('',(28.1576786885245,-1.87444148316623,14.5000000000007));
#441=B_SPLINE_CURVE_WITH_KNOTS('',3,(#431,#432,#433,#434,#435,#436,#437,#438,#439,#440),
.UNSPECIFIED.,.F.,.F.,(4,2,2,2,4),(0.,0.283456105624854,0.566040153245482,0.848370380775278,
1.13156772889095),.UNSPECIFIED.);
#442=CARTESIAN_POINT('',(28.1576786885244,-1.87444148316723,14.4999999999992));
#443=VERTEX_POINT('',#442);
#444=EDGE_CURVE('E114',#428,#443,#441,.T.);
#445=ORIENTED_EDGE('',*,*,#444,.T.);
#446=CARTESIAN_POINT('',(0.,0.,14.5));
#447=DIRECTION('',(0.,0.,-1.));
#448=DIRECTION('',(0.,-1.,0.));
#449=AXIS2_PLACEMENT_3D('',#446,#447,#448);
#450=CIRCLE('',#449,28.22);
#451=CARTESIAN_POINT('',(28.0927606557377,-2.67678888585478,14.5));
#452=VERTEX_POINT('',#451);
#453=EDGE_CURVE('E111',#452,#443,#450,.F.);
#454=ORIENTED_EDGE('',*,*,#453,.F.);
#455=DIRECTION('',(0.,0.,-1.));
#456=VECTOR('',#455,1.);
#457=CARTESIAN_POINT('',(28.0927606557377,-2.67678888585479,16.2811848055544));
#458=LINE('',#457,#456);
#459=CARTESIAN_POINT('',(28.0927606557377,-2.67678888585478,12.6));
#460=VERTEX_POINT('',#459);
#461=EDGE_CURVE('E101',#460,#452,#458,.F.);
#462=ORIENTED_EDGE('',*,*,#461,.F.);
#463=CARTESIAN_POINT('',(0.,0.,12.6));
#464=DIRECTION('',(0.,0.,-1.));
#465=DIRECTION('',(0.,-1.,0.));
#466=AXIS2_PLACEMENT_3D('',#463,#464,#465);
#467=CIRCLE('',#466,28.22);
#468=CARTESIAN_POINT('',(28.0927606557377,2.67678888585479,12.6));
#469=VERTEX_POINT('',#468);
#470=EDGE_CURVE('E83',#469,#460,#467,.F.);
#471=ORIENTED_EDGE('',*,*,#470,.F.);
#472=DIRECTION('',(0.,0.,-1.));
#473=VECTOR('',#472,1.);
#474=CARTESIAN_POINT('',(28.0927606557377,2.6767888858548,16.2811848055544));
#475=LINE('',#474,#473);
#476=CARTESIAN_POINT('',(28.0927606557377,2.67678888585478,14.5));
#477=VERTEX_POINT('',#476);
#478=EDGE_CURVE('E94',#477,#469,#475,.T.);
#479=ORIENTED_EDGE('',*,*,#478,.F.);
#480=CARTESIAN_POINT('',(0.,0.,14.5));
#481=DIRECTION('',(0.,0.,-1.));
#482=DIRECTION('',(0.,-1.,0.));
#483=AXIS2_PLACEMENT_3D('',#480,#481,#482);
#484=CIRCLE('',#483,28.22);
#485=CARTESIAN_POINT('',(28.1576786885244,1.87444148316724,14.4999999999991));
#486=VERTEX_POINT('',#485);
#487=EDGE_CURVE('E105',#477,#486,#484,.T.);
#488=ORIENTED_EDGE('',*,*,#487,.T.);
#489=CARTESIAN_POINT('',(28.2061340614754,0.88453451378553,15.0415000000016));
#490=CARTESIAN_POINT('',(28.2033697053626,0.972611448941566,15.0071759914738));
#491=CARTESIAN_POINT('',(28.2002462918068,1.05911764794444,14.9691713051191));
#492=CARTESIAN_POINT('',(28.1933520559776,1.22903996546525,14.8874249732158));
#493=CARTESIAN_POINT('',(28.1895832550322,1.3124647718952,14.8437013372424));
#494=CARTESIAN_POINT('',(28.1814548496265,1.47673995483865,14.7519530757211));
#495=CARTESIAN_POINT('',(28.177095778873,1.55759257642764,14.7039323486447));
#496=CARTESIAN_POINT('',(28.1678059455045,1.71741116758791,14.6043552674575));
#497=CARTESIAN_POINT('',(28.1628734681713,1.79637058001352,14.5527885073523));
#498=CARTESIAN_POINT('',(28.1576786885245,1.87444148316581,14.500000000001));
#499=B_SPLINE_CURVE_WITH_KNOTS('',3,(#489,#490,#491,#492,#493,#494,#495,#496,#497,#498),
.UNSPECIFIED.,.F.,.F.,(4,2,2,2,4),(0.,0.283456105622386,0.566040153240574,0.848370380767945,
1.13156772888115),.UNSPECIFIED.);
#500=CARTESIAN_POINT('',(28.2061340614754,0.884534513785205,15.0415000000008));
#501=VERTEX_POINT('',#500);
#502=EDGE_CURVE('E560',#501,#486,#499,.T.);
#503=ORIENTED_EDGE('',*,*,#502,.F.);
#504=DIRECTION('',(0.,0.,1.));
#505=VECTOR('',#504,1.);
#506=CARTESIAN_POINT('',(28.2061340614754,0.884534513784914,21.75));
#507=LINE('',#506,#505);
#508=CARTESIAN_POINT('',(28.2061340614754,0.884534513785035,16.0720000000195));
#509=VERTEX_POINT('',#508);
#510=EDGE_CURVE('E698',#501,#509,#507,.T.);
#511=ORIENTED_EDGE('',*,*,#510,.T.);
#512=CARTESIAN_POINT('',(28.0367714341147,3.21058367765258,17.6601458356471));
#513=CARTESIAN_POINT('',(28.0459385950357,3.13052012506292,17.5910607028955));
#514=CARTESIAN_POINT('',(28.0548094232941,3.05003051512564,17.5224225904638));
#515=CARTESIAN_POINT('',(28.0719526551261,2.88799766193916,17.3862846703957));
#516=CARTESIAN_POINT('',(28.0802249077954,2.80645415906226,17.318785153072));
#517=CARTESIAN_POINT('',(28.096219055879,2.64154950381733,17.1847137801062));
#518=CARTESIAN_POINT('',(28.1039364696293,2.55817940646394,17.1181523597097));
#519=CARTESIAN_POINT('',(28.1187408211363,2.38996754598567,16.9868539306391));
#520=CARTESIAN_POINT('',(28.1258278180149,2.3051259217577,16.9221167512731));
#521=CARTESIAN_POINT('',(28.1390801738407,2.13714161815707,16.7975584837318));
#522=CARTESIAN_POINT('',(28.1452712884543,2.05407009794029,16.7376445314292));
#523=CARTESIAN_POINT('',(28.1570361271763,1.88595270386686,16.620594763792));
#524=CARTESIAN_POINT('',(28.1626099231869,1.80090706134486,16.5634586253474));
#525=CARTESIAN_POINT('',(28.1730975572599,1.62862099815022,16.452953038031));
#526=CARTESIAN_POINT('',(28.1780128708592,1.54138602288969,16.3995752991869));
#527=CARTESIAN_POINT('',(28.187150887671,1.36411126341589,16.2976734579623));
#528=CARTESIAN_POINT('',(28.1913739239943,1.27407285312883,16.249147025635));
#529=CARTESIAN_POINT('',(28.1984682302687,1.10489857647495,16.1656178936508));
#530=CARTESIAN_POINT('',(28.201447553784,1.02623141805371,16.1296844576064));
#531=CARTESIAN_POINT('',(28.2068078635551,0.866470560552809,16.0638474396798));
#532=CARTESIAN_POINT('',(28.209189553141,0.785379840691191,16.033936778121));
#533=CARTESIAN_POINT('',(28.2133251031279,0.619412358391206,15.9812583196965));
#534=CARTESIAN_POINT('',(28.2150684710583,0.53449605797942,15.9586105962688));
#535=CARTESIAN_POINT('',(28.2171203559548,0.405443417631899,15.9317189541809));
#536=CARTESIAN_POINT('',(28.2177112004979,0.362038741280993,15.923924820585));
#537=CARTESIAN_POINT('',(28.2186955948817,0.274819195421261,15.9108914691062));
#538=CARTESIAN_POINT('',(28.2190890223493,0.2310040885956,15.9056538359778));
#539=CARTESIAN_POINT('',(28.2193800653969,0.187052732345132,15.9017779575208));
#540=B_SPLINE_CURVE_WITH_KNOTS('',3,(#512,#513,#514,#515,#516,#517,#518,#519,#520,#521,#522,
#523,#524,#525,#526,#527,#528,#529,#530,#531,#532,#533,#534,#535,#536,#537,#538,#539),
.UNSPECIFIED.,.F.,.F.,(4,2,2,2,2,2,2,2,2,2,2,2,2,4),(0.,0.318442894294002,0.636965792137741,
0.957824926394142,1.27865393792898,1.58643958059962,1.8941893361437,2.20123751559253,
2.50813751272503,2.76755059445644,3.02665693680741,3.28984912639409,3.4220888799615,
3.55441050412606),.UNSPECIFIED.);
#541=CARTESIAN_POINT('',(28.1576786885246,1.87444148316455,16.6135));
#542=VERTEX_POINT('',#541);
#543=EDGE_CURVE('E31',#542,#509,#540,.T.);
#544=ORIENTED_EDGE('',*,*,#543,.F.);
#545=DIRECTION('',(0.,0.,-1.));
#546=VECTOR('',#545,1.);
#547=CARTESIAN_POINT('',(28.1576786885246,1.87444148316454,16.2811848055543));
#548=LINE('',#547,#546);
#549=CARTESIAN_POINT('',(28.1576786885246,1.87444148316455,19.9623696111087));
#550=VERTEX_POINT('',#549);
#551=EDGE_CURVE('E309',#550,#542,#548,.T.);
#552=ORIENTED_EDGE('',*,*,#551,.F.);
#553=CARTESIAN_POINT('',(0.,0.,19.9623696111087));
#554=DIRECTION('',(0.,0.,-1.));
#555=DIRECTION('',(0.,-1.,0.));
#556=AXIS2_PLACEMENT_3D('',#553,#554,#555);
#557=CIRCLE('',#556,28.22);
#558=CARTESIAN_POINT('',(28.1576786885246,-1.87444148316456,19.9623696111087));
#559=VERTEX_POINT('',#558);
#560=EDGE_CURVE('E711',#559,#550,#557,.T.);
#561=ORIENTED_EDGE('',*,*,#560,.F.);
#562=DIRECTION('',(0.,0.,-1.));
#563=VECTOR('',#562,1.);
#564=CARTESIAN_POINT('',(28.1576786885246,-1.87444148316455,16.2811848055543));
#565=LINE('',#564,#563);
#566=EDGE_CURVE('E321',#420,#559,#565,.F.);
#567=ORIENTED_EDGE('',*,*,#566,.F.);
#568=EDGE_LOOP('',(#422,#430,#445,#454,#462,#471,#479,#488,#503,#511,#544,#552,#561,#567));
#569=FACE_BOUND('',#568,.T.);
#570=ADVANCED_FACE('F108',(#569),#381,.F.);
#571=CARTESIAN_POINT('',(30.5,0.,21.75));
#572=DIRECTION('',(0.,0.,1.));
#573=DIRECTION('',(0.,1.,0.));
#574=AXIS2_PLACEMENT_3D('',#571,#572,#573);
#575=CYLINDRICAL_SURFACE('',#574,2.4585);
#576=CARTESIAN_POINT('',(30.5,0.,16.0720000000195));
#577=DIRECTION('',(0.,0.,1.));
#578=DIRECTION('',(0.,1.,0.));
#579=AXIS2_PLACEMENT_3D('',#576,#577,#578);
#580=CIRCLE('',#579,2.4585);
#581=EDGE_CURVE('E38',#509,#418,#580,.F.);
#582=ORIENTED_EDGE('',*,*,#581,.F.);
#583=ORIENTED_EDGE('',*,*,#510,.F.);
#584=CARTESIAN_POINT('',(30.5,0.,15.0415));
#585=DIRECTION('',(0.,0.,1.));
#586=DIRECTION('',(0.,1.,0.));
#587=AXIS2_PLACEMENT_3D('',#584,#585,#586);
#588=CIRCLE('',#587,2.4585);
#589=EDGE_CURVE('E701',#428,#501,#588,.T.);
#590=ORIENTED_EDGE('',*,*,#589,.F.);
#591=ORIENTED_EDGE('',*,*,#429,.F.);
#592=EDGE_LOOP('',(#582,#583,#590,#591));
#593=FACE_BOUND('',#592,.T.);
#594=ADVANCED_FACE('F542',(#593),#575,.F.);
#595=CARTESIAN_POINT('',(30.5,0.,14.5000000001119));
#596=DIRECTION('',(0.,0.,-1.));
#597=DIRECTION('',(0.,-1.,0.));
#598=AXIS2_PLACEMENT_3D('',#595,#596,#597);
#599=CONICAL_SURFACE('',#598,2.99999999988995,0.785398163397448);
#600=ORIENTED_EDGE('',*,*,#589,.T.);
#601=ORIENTED_EDGE('',*,*,#502,.T.);
#602=CARTESIAN_POINT('',(30.5,0.,14.4999999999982));
#603=DIRECTION('',(0.,0.,-1.));
#604=DIRECTION('',(0.,-1.,0.));
#605=AXIS2_PLACEMENT_3D('',#602,#603,#604);
#606=CIRCLE('',#605,3.00000000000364);
#607=EDGE_CURVE('E572',#443,#486,#606,.F.);
#608=ORIENTED_EDGE('',*,*,#607,.F.);
#609=ORIENTED_EDGE('',*,*,#444,.F.);
#610=EDGE_LOOP('',(#600,#601,#608,#609));
#611=FACE_BOUND('',#610,.T.);
#612=ADVANCED_FACE('F338',(#611),#599,.F.);
#613=CARTESIAN_POINT('',(33.8,0.,14.5));
#614=DIRECTION('',(0.,0.,1.));
#615=DIRECTION('',(0.,1.,0.));
#616=AXIS2_PLACEMENT_3D('',#613,#614,#615);
#617=PLANE('',#616);
#618=ORIENTED_EDGE('',*,*,#453,.T.);
#619=ORIENTED_EDGE('',*,*,#607,.T.);
#620=ORIENTED_EDGE('',*,*,#487,.F.);
#621=CARTESIAN_POINT('',(30.5,0.,14.5));
#622=DIRECTION('',(0.,0.,1.));
#623=DIRECTION('',(0.,1.,0.));
#624=AXIS2_PLACEMENT_3D('',#621,#622,#623);
#625=CIRCLE('',#624,3.6);
#626=EDGE_CURVE('E580',#477,#452,#625,.F.);
#627=ORIENTED_EDGE('',*,*,#626,.T.);
#628=EDGE_LOOP('',(#618,#619,#620,#627));
#629=FACE_BOUND('',#628,.T.);
#630=ADVANCED_FACE('F335',(#629),#617,.F.);
#631=CARTESIAN_POINT('',(30.5,0.,7.25));
#632=DIRECTION('',(0.,0.,1.));
#633=DIRECTION('',(0.,1.,0.));
#634=AXIS2_PLACEMENT_3D('',#631,#632,#633);
#635=CYLINDRICAL_SURFACE('',#634,3.6);
#636=ORIENTED_EDGE('',*,*,#626,.F.);
#637=ORIENTED_EDGE('',*,*,#478,.T.);
#638=CARTESIAN_POINT('',(28.0927606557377,2.67678888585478,12.6));
#639=CARTESIAN_POINT('',(28.1657295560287,2.7423893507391,12.5211327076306));
#640=CARTESIAN_POINT('',(28.2404137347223,2.804179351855,12.4407479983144));
#641=CARTESIAN_POINT('',(28.3924583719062,2.92017160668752,12.2778114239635));
#642=CARTESIAN_POINT('',(28.469807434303,2.97440212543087,12.1952690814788));
#643=CARTESIAN_POINT('',(28.6269869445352,3.07580331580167,12.0282793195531));
#644=CARTESIAN_POINT('',(28.7068171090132,3.12297479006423,11.9438321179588));
#645=CARTESIAN_POINT('',(28.8689265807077,3.2106236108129,11.7731091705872));
#646=CARTESIAN_POINT('',(28.9512141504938,3.25107442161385,11.6868276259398));
#647=CARTESIAN_POINT('',(29.0344,3.28816311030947,11.6));
#648=B_SPLINE_CURVE_WITH_KNOTS('',3,(#638,#639,#640,#641,#642,#643,#644,#645,#646,#647),
.UNSPECIFIED.,.F.,.F.,(4,2,2,2,4),(0.,0.377528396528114,0.753605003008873,1.12963881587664,
1.50712377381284),.UNSPECIFIED.);
#649=CARTESIAN_POINT('',(29.0344,3.28816311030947,11.6));
#650=VERTEX_POINT('',#649);
#651=EDGE_CURVE('E89',#469,#650,#648,.T.);
#652=ORIENTED_EDGE('',*,*,#651,.T.);
#653=CARTESIAN_POINT('',(30.5,0.,11.6));
#654=DIRECTION('',(0.,0.,1.));
#655=DIRECTION('',(0.,1.,0.));
#656=AXIS2_PLACEMENT_3D('',#653,#654,#655);
#657=CIRCLE('',#656,3.6);
#658=CARTESIAN_POINT('',(29.0344,-3.28816311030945,11.6));
#659=VERTEX_POINT('',#658);
#660=EDGE_CURVE('E103',#659,#650,#657,.T.);
#661=ORIENTED_EDGE('',*,*,#660,.F.);
#662=CARTESIAN_POINT('',(28.0927606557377,-2.67678888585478,12.6));
#663=CARTESIAN_POINT('',(28.1657295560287,-2.7423893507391,12.5211327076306));
#664=CARTESIAN_POINT('',(28.2404137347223,-2.804179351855,12.4407479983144));
#665=CARTESIAN_POINT('',(28.3924583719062,-2.92017160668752,12.2778114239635));
#666=CARTESIAN_POINT('',(28.469807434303,-2.97440212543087,12.1952690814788));
#667=CARTESIAN_POINT('',(28.6269869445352,-3.07580331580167,12.0282793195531));
#668=CARTESIAN_POINT('',(28.7068171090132,-3.12297479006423,11.9438321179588));
#669=CARTESIAN_POINT('',(28.8689265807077,-3.2106236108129,11.7731091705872));
#670=CARTESIAN_POINT('',(28.9512141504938,-3.25107442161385,11.6868276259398));
#671=CARTESIAN_POINT('',(29.0344,-3.28816311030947,11.6));
#672=B_SPLINE_CURVE_WITH_KNOTS('',3,(#662,#663,#664,#665,#666,#667,#668,#669,#670,#671),
.UNSPECIFIED.,.F.,.F.,(4,2,2,2,4),(0.,0.377528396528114,0.753605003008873,1.12963881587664,
1.50712377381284),.UNSPECIFIED.);
#673=EDGE_CURVE('E87',#460,#659,#672,.T.);
#674=ORIENTED_EDGE('',*,*,#673,.F.);
#675=ORIENTED_EDGE('',*,*,#461,.T.);
#676=EDGE_LOOP('',(#636,#637,#652,#661,#674,#675));
#677=FACE_BOUND('',#676,.T.);
#678=ADVANCED_FACE('F100',(#677),#635,.F.);
#679=CARTESIAN_POINT('',(0.,0.,11.6));
#680=DIRECTION('',(0.,0.,-1.));
#681=DIRECTION('',(0.,-1.,0.));
#682=AXIS2_PLACEMENT_3D('',#679,#680,#681);
#683=CONICAL_SURFACE('',#682,29.22,0.785398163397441);
#684=CARTESIAN_POINT('',(0.,0.,11.6));
#685=DIRECTION('',(0.,0.,-1.));
#686=DIRECTION('',(0.,-1.,0.));
#687=AXIS2_PLACEMENT_3D('',#684,#685,#686);
#688=CIRCLE('',#687,29.22);
#689=EDGE_CURVE('E117',#650,#659,#688,.F.);
#690=ORIENTED_EDGE('',*,*,#689,.F.);
#691=ORIENTED_EDGE('',*,*,#651,.F.);
#692=ORIENTED_EDGE('',*,*,#470,.T.);
#693=ORIENTED_EDGE('',*,*,#673,.T.);
#694=EDGE_LOOP('',(#690,#691,#692,#693));
#695=FACE_BOUND('',#694,.T.);
#696=ADVANCED_FACE('F86',(#695),#683,.F.);
#697=CARTESIAN_POINT('',(0.,0.,19.9623696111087));
#698=DIRECTION('',(0.,0.,1.));
#699=DIRECTION('',(0.,1.,0.));
#700=AXIS2_PLACEMENT_3D('',#697,#698,#699);
#701=TOROIDAL_SURFACE('',#700,26.72,1.5);
#702=CARTESIAN_POINT('',(28.1576786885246,-1.87444148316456,19.9623696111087));
#703=CARTESIAN_POINT('',(28.1576817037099,-1.87444049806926,19.9925254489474));
#704=CARTESIAN_POINT('',(28.1568363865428,-1.87338941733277,20.022665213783));
#705=CARTESIAN_POINT('',(28.1534856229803,-1.86919262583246,20.0826982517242));
#706=CARTESIAN_POINT('',(28.1509805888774,-1.86604743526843,20.1125915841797));
#707=CARTESIAN_POINT('',(28.1410626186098,-1.8535193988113,20.2013117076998));
#708=CARTESIAN_POINT('',(28.1312460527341,-1.84104387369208,20.2594787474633));
#709=CARTESIAN_POINT('',(28.106012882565,-1.80810637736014,20.372150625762));
#710=CARTESIAN_POINT('',(28.090597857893,-1.78764665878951,20.4266564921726));
#711=CARTESIAN_POINT('',(28.0554175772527,-1.73922643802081,20.5307113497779));
#712=CARTESIAN_POINT('',(28.0356505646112,-1.71126290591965,20.5802583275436));
#713=CARTESIAN_POINT('',(27.9929336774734,-1.64805629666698,20.6742159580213));
#714=CARTESIAN_POINT('',(27.9699375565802,-1.61270295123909,20.7185307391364));
#715=CARTESIAN_POINT('',(27.9226176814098,-1.53594882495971,20.8007113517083));
#716=CARTESIAN_POINT('',(27.8982933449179,-1.49454537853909,20.8385743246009));
#717=CARTESIAN_POINT('',(27.8390774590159,-1.38732918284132,20.9232382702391));
#718=CARTESIAN_POINT('',(27.8042471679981,-1.31879386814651,20.9666380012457));
#719=CARTESIAN_POINT('',(27.7381093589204,-1.17402137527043,21.0418180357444));
#720=CARTESIAN_POINT('',(27.7068101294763,-1.09776684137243,21.0735713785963));
#721=CARTESIAN_POINT('',(27.6590002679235,-0.965389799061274,21.1187603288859));
#722=CARTESIAN_POINT('',(27.6409683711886,-0.91066644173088,21.1348037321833));
#723=CARTESIAN_POINT('',(27.6078690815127,-0.799342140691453,21.1630546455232));
#724=CARTESIAN_POINT('',(27.5928027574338,-0.742740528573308,21.1752607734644));
#725=CARTESIAN_POINT('',(27.5659074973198,-0.628147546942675,21.1963530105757));
#726=CARTESIAN_POINT('',(27.5540801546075,-0.570155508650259,21.2052374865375));
#727=CARTESIAN_POINT('',(27.5338338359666,-0.453191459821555,21.2200945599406));
#728=CARTESIAN_POINT('',(27.5254162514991,-0.394219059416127,21.2260659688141));
#729=CARTESIAN_POINT('',(27.5119412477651,-0.274284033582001,21.2354946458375));
#730=CARTESIAN_POINT('',(27.5069673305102,-0.213307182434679,21.2388896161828));
#731=CARTESIAN_POINT('',(27.5007571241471,-0.0910508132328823,21.2431136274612));
#732=CARTESIAN_POINT('',(27.4995224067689,-0.0297711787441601,21.2439415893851));
#733=CARTESIAN_POINT('',(27.5008079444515,0.092732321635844,21.2430733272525));
#734=CARTESIAN_POINT('',(27.5033282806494,0.153956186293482,21.2413770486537));
#735=CARTESIAN_POINT('',(27.5120955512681,0.275983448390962,21.2353699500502));
#736=CARTESIAN_POINT('',(27.5183408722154,0.336787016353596,21.2310602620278));
#737=CARTESIAN_POINT('',(27.5341374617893,0.455041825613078,21.2198456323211));
#738=CARTESIAN_POINT('',(27.5435351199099,0.512524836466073,21.2130601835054));
#739=CARTESIAN_POINT('',(27.5655572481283,0.626425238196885,21.1965749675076));
#740=CARTESIAN_POINT('',(27.5781803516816,0.682843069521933,21.1868764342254));
#741=CARTESIAN_POINT('',(27.6064627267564,0.794189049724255,21.1641502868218));
#742=CARTESIAN_POINT('',(27.6221194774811,0.849118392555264,21.151125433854));
#743=CARTESIAN_POINT('',(27.6561805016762,0.95702359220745,21.1212355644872));
#744=CARTESIAN_POINT('',(27.6745837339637,1.01000017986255,21.104372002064));
#745=CARTESIAN_POINT('',(27.7221798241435,1.13576177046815,21.0579890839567));
#746=CARTESIAN_POINT('',(27.7526072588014,1.20725775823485,21.0261466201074));
#747=CARTESIAN_POINT('',(27.8163352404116,1.34296075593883,20.9516755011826));
#748=CARTESIAN_POINT('',(27.8496310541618,1.40717938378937,20.9090643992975));
#749=CARTESIAN_POINT('',(27.9098533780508,1.51466160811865,20.8210539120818));
#750=CARTESIAN_POINT('',(27.9367924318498,1.55959073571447,20.7777093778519));
#751=CARTESIAN_POINT('',(27.9885866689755,1.64169380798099,20.6830769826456));
#752=CARTESIAN_POINT('',(28.013442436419,1.67886993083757,20.6317913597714));
#753=CARTESIAN_POINT('',(28.0589992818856,1.74445734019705,20.5216385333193));
#754=CARTESIAN_POINT('',(28.0796699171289,1.77280515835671,20.4627205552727));
#755=CARTESIAN_POINT('',(28.1145105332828,1.81942234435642,20.3392444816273));
#756=CARTESIAN_POINT('',(28.1286877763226,1.83770297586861,20.2746927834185));
#757=CARTESIAN_POINT('',(28.1450577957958,1.85858734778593,20.1683174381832));
#758=CARTESIAN_POINT('',(28.1497696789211,1.86452693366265,20.1274949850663));
#759=CARTESIAN_POINT('',(28.1560876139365,1.87245370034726,20.0452481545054));
#760=CARTESIAN_POINT('',(28.1576949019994,1.87444245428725,20.0038240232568));
#761=CARTESIAN_POINT('',(28.1576786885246,1.87444148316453,19.9623696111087));
#762=B_SPLINE_CURVE_WITH_KNOTS('',3,(#702,#703,#704,#705,#706,#707,#708,#709,#710,#711,#712,
#713,#714,#715,#716,#717,#718,#719,#720,#721,#722,#723,#724,#725,#726,#727,#728,#729,#730,#731,
#732,#733,#734,#735,#736,#737,#738,#739,#740,#741,#742,#743,#744,#745,#746,#747,#748,#749,#750,
#751,#752,#753,#754,#755,#756,#757,#758,#759,#760,#761),.UNSPECIFIED.,.F.,.F.,(4,2,2,2,2,2,2,2,
2,2,2,2,2,2,2,2,2,2,2,2,2,2,2,2,2,2,2,2,2,4),(0.,0.0904058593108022,0.180789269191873,
0.360668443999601,0.54049690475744,0.720398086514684,0.903204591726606,1.08609188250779,
1.34947725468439,1.6134685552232,1.79268030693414,1.97195653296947,2.15132079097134,
2.33075817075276,2.51440705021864,2.69813311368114,2.88186314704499,3.06551365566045,
3.24127162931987,3.41695526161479,3.59249353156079,3.767965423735,4.01896690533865,
4.26956185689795,4.47271809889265,4.67581718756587,4.88034437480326,5.08464225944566,
5.20891903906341,5.33314632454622),.UNSPECIFIED.);
#763=EDGE_CURVE('E312',#559,#550,#762,.T.);
#764=ORIENTED_EDGE('',*,*,#763,.F.);
#765=ORIENTED_EDGE('',*,*,#560,.T.);
#766=EDGE_LOOP('',(#764,#765));
#767=FACE_BOUND('',#766,.T.);
#768=CARTESIAN_POINT('',(0.,0.,21.439581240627));
#769=DIRECTION('',(0.,0.,1.));
#770=DIRECTION('',(0.,1.,0.));
#771=AXIS2_PLACEMENT_3D('',#768,#769,#770);
#772=CIRCLE('',#771,26.4595277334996);
#773=CARTESIAN_POINT('',(0.,26.4595277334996,21.439581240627));
#774=VERTEX_POINT('',#773);
#775=EDGE_CURVE('E123',#774,#774,#772,.F.);
#776=ORIENTED_EDGE('',*,*,#775,.F.);
#777=EDGE_LOOP('',(#776));
#778=FACE_BOUND('',#777,.T.);
#779=ADVANCED_FACE('F326',(#767,#778),#701,.F.);
#780=CARTESIAN_POINT('',(0.,0.,21.439581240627));
#781=DIRECTION('',(0.,0.,1.));
#782=DIRECTION('',(0.,1.,0.));
#783=AXIS2_PLACEMENT_3D('',#780,#781,#782);
#784=CONICAL_SURFACE('',#783,26.4595277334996,1.39626340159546);
#785=CARTESIAN_POINT('',(0.,0.,19.1974406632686));
#786=DIRECTION('',(0.,0.,1.));
#787=DIRECTION('',(-1.,0.,0.));
#788=AXIS2_PLACEMENT_3D('',#785,#786,#787);
#789=CIRCLE('',#788,13.7437166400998);
#790=CARTESIAN_POINT('',(-13.7437166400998,0.,19.1974406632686));
#791=VERTEX_POINT('',#790);
#792=EDGE_CURVE('E129',#791,#791,#789,.T.);
#793=ORIENTED_EDGE('',*,*,#792,.T.);
#794=EDGE_LOOP('',(#793));
#795=FACE_BOUND('',#794,.T.);
#796=ORIENTED_EDGE('',*,*,#775,.T.);
#797=EDGE_LOOP('',(#796));
#798=FACE_BOUND('',#797,.T.);
#799=ADVANCED_FACE('F331',(#795,#798),#784,.T.);
#800=CARTESIAN_POINT('',(-33.5250725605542,0.,11.6));
#801=DIRECTION('',(0.,0.,-1.));
#802=DIRECTION('',(0.,-1.,0.));
#803=AXIS2_PLACEMENT_3D('',#800,#801,#802);
#804=PLANE('',#803);
#805=CARTESIAN_POINT('',(0.,0.,11.6));
#806=DIRECTION('',(0.,0.,1.));
#807=DIRECTION('',(0.,1.,0.));
#808=AXIS2_PLACEMENT_3D('',#805,#806,#807);
#809=CIRCLE('',#808,37.8301451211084);
#810=CARTESIAN_POINT('',(0.,37.8301451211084,11.6));
#811=VERTEX_POINT('',#810);
#812=EDGE_CURVE('E128',#811,#811,#809,.F.);
#813=ORIENTED_EDGE('',*,*,#812,.T.);
#814=EDGE_LOOP('',(#813));
#815=FACE_BOUND('',#814,.T.);
#816=ORIENTED_EDGE('',*,*,#689,.T.);
#817=ORIENTED_EDGE('',*,*,#660,.T.);
#818=EDGE_LOOP('',(#816,#817));
#819=FACE_BOUND('',#818,.T.);
#820=ADVANCED_FACE('F142',(#815,#819),#804,.T.);
#821=CARTESIAN_POINT('',(0.,0.,18.3111136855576));
#822=DIRECTION('',(0.,0.,1.));
#823=DIRECTION('',(0.,1.,0.));
#824=AXIS2_PLACEMENT_3D('',#821,#822,#823);
#825=TOROIDAL_SURFACE('',#824,13.9,0.9);
#826=CARTESIAN_POINT('',(0.,0.,18.3111136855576));
#827=DIRECTION('',(0.,0.,1.));
#828=DIRECTION('',(0.,1.,0.));
#829=AXIS2_PLACEMENT_3D('',#826,#827,#828);
#830=CIRCLE('',#829,13.);
#831=CARTESIAN_POINT('',(0.,13.,18.3111136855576));
#832=VERTEX_POINT('',#831);
#833=EDGE_CURVE('E132',#832,#832,#830,.F.);
#834=ORIENTED_EDGE('',*,*,#833,.F.);
#835=EDGE_LOOP('',(#834));
#836=FACE_BOUND('',#835,.T.);
#837=ORIENTED_EDGE('',*,*,#792,.F.);
#838=EDGE_LOOP('',(#837));
#839=FACE_BOUND('',#838,.T.);
#840=ADVANCED_FACE('F137',(#836,#839),#825,.F.);
#841=CARTESIAN_POINT('',(0.,0.,20.3423312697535));
#842=DIRECTION('',(0.,0.,1.));
#843=DIRECTION('',(0.,1.,0.));
#844=AXIS2_PLACEMENT_3D('',#841,#842,#843);
#845=CONICAL_SURFACE('',#844,38.595,0.0872664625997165);
#846=CARTESIAN_POINT('',(0.,0.,20.3423312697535));
#847=DIRECTION('',(0.,0.,-1.));
#848=DIRECTION('',(-1.,0.,0.));
#849=AXIS2_PLACEMENT_3D('',#846,#847,#848);
#850=CIRCLE('',#849,38.595);
#851=CARTESIAN_POINT('',(-38.595,0.,20.3423312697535));
#852=VERTEX_POINT('',#851);
#853=EDGE_CURVE('E106',#852,#852,#850,.T.);
#854=ORIENTED_EDGE('',*,*,#853,.T.);
#855=EDGE_LOOP('',(#854));
#856=FACE_BOUND('',#855,.T.);
#857=ORIENTED_EDGE('',*,*,#812,.F.);
#858=EDGE_LOOP('',(#857));
#859=FACE_BOUND('',#858,.T.);
#860=ADVANCED_FACE('F141',(#856,#859),#845,.T.);
#861=CARTESIAN_POINT('',(0.,0.,9.25555684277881));
#862=DIRECTION('',(0.,0.,-1.));
#863=DIRECTION('',(0.,-1.,0.));
#864=AXIS2_PLACEMENT_3D('',#861,#862,#863);
#865=CYLINDRICAL_SURFACE('',#864,13.);
#866=CARTESIAN_POINT('',(0.,0.,0.200000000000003));
#867=DIRECTION('',(0.,0.,-1.));
#868=DIRECTION('',(0.,-1.,0.));
#869=AXIS2_PLACEMENT_3D('',#866,#867,#868);
#870=CIRCLE('',#869,13.);
#871=CARTESIAN_POINT('',(0.,-13.,0.200000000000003));
#872=VERTEX_POINT('',#871);
#873=EDGE_CURVE('E592',#872,#872,#870,.F.);
#874=ORIENTED_EDGE('',*,*,#873,.T.);
#875=EDGE_LOOP('',(#874));
#876=FACE_BOUND('',#875,.T.);
#877=ORIENTED_EDGE('',*,*,#833,.T.);
#878=EDGE_LOOP('',(#877));
#879=FACE_BOUND('',#878,.T.);
#880=ADVANCED_FACE('F145',(#876,#879),#865,.T.);
#881=CARTESIAN_POINT('',(0.,0.,20.3));
#882=DIRECTION('',(0.,0.,-1.));
#883=DIRECTION('',(0.,-1.,0.));
#884=AXIS2_PLACEMENT_3D('',#881,#882,#883);
#885=CONICAL_SURFACE('',#884,39.0788486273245,1.48352986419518);
#886=CARTESIAN_POINT('',(0.,0.,20.3));
#887=DIRECTION('',(0.,0.,-1.));
#888=DIRECTION('',(-1.,0.,0.));
#889=AXIS2_PLACEMENT_3D('',#886,#887,#888);
#890=CIRCLE('',#889,39.0788486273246);
#891=CARTESIAN_POINT('',(-39.0788486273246,0.,20.3));
#892=VERTEX_POINT('',#891);
#893=EDGE_CURVE('E112',#892,#892,#890,.T.);
#894=ORIENTED_EDGE('',*,*,#893,.T.);
#895=EDGE_LOOP('',(#894));
#896=FACE_BOUND('',#895,.T.);
#897=ORIENTED_EDGE('',*,*,#853,.F.);
#898=EDGE_LOOP('',(#897));
#899=FACE_BOUND('',#898,.T.);
#900=ADVANCED_FACE('F148',(#896,#899),#885,.F.);
#901=CARTESIAN_POINT('',(-11.,0.,0.2));
#902=DIRECTION('',(0.,0.,-1.));
#903=DIRECTION('',(-1.,0.,0.));
#904=AXIS2_PLACEMENT_3D('',#901,#902,#903);
#905=PLANE('',#904);
#906=CARTESIAN_POINT('',(0.,0.,0.2));
#907=DIRECTION('',(0.,0.,-1.));
#908=DIRECTION('',(0.,-1.,0.));
#909=AXIS2_PLACEMENT_3D('',#906,#907,#908);
#910=CIRCLE('',#909,9.);
#911=CARTESIAN_POINT('',(0.,-9.,0.2));
#912=VERTEX_POINT('',#911);
#913=EDGE_CURVE('E595',#912,#912,#910,.F.);
#914=ORIENTED_EDGE('',*,*,#913,.T.);
#915=EDGE_LOOP('',(#914));
#916=FACE_BOUND('',#915,.T.);
#917=ORIENTED_EDGE('',*,*,#873,.F.);
#918=EDGE_LOOP('',(#917));
#919=FACE_BOUND('',#918,.T.);
#920=ADVANCED_FACE('F150',(#916,#919),#905,.T.);
#921=CARTESIAN_POINT('',(0.,0.,11.6));
#922=DIRECTION('',(0.,0.,-1.));
#923=DIRECTION('',(0.,-1.,0.));
#924=AXIS2_PLACEMENT_3D('',#921,#922,#923);
#925=CONICAL_SURFACE('',#924,39.84,0.087266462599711);
#926=CARTESIAN_POINT('',(0.,0.,11.6));
#927=DIRECTION('',(0.,0.,-1.));
#928=DIRECTION('',(0.,-1.,0.));
#929=AXIS2_PLACEMENT_3D('',#926,#927,#928);
#930=CIRCLE('',#929,39.84);
#931=CARTESIAN_POINT('',(0.,-39.84,11.6));
#932=VERTEX_POINT('',#931);
#933=EDGE_CURVE('E93',#932,#932,#930,.T.);
#934=ORIENTED_EDGE('',*,*,#933,.T.);
#935=EDGE_LOOP('',(#934));
#936=FACE_BOUND('',#935,.T.);
#937=ORIENTED_EDGE('',*,*,#893,.F.);
#938=EDGE_LOOP('',(#937));
#939=FACE_BOUND('',#938,.T.);
#940=ADVANCED_FACE('F153',(#936,#939),#925,.F.);
#941=CARTESIAN_POINT('',(0.,0.,0.1));
#942=DIRECTION('',(0.,0.,-1.));
#943=DIRECTION('',(0.,-1.,0.));
#944=AXIS2_PLACEMENT_3D('',#941,#942,#943);
#945=CYLINDRICAL_SURFACE('',#944,9.);
#946=ORIENTED_EDGE('',*,*,#913,.F.);
#947=EDGE_LOOP('',(#946));
#948=FACE_BOUND('',#947,.T.);
#949=CARTESIAN_POINT('',(0.,0.,0.));
#950=DIRECTION('',(0.,0.,-1.));
#951=DIRECTION('',(0.,-1.,0.));
#952=AXIS2_PLACEMENT_3D('',#949,#950,#951);
#953=CIRCLE('',#952,9.);
#954=CARTESIAN_POINT('',(0.,-9.,0.));
#955=VERTEX_POINT('',#954);
#956=EDGE_CURVE('E598',#955,#955,#953,.F.);
#957=ORIENTED_EDGE('',*,*,#956,.T.);
#958=EDGE_LOOP('',(#957));
#959=FACE_BOUND('',#958,.T.);
#960=ADVANCED_FACE('F155',(#948,#959),#945,.T.);
#961=CARTESIAN_POINT('',(0.,0.,10.3));
#962=DIRECTION('',(0.,0.,-1.));
#963=DIRECTION('',(0.,-1.,0.));
#964=AXIS2_PLACEMENT_3D('',#961,#962,#963);
#965=CYLINDRICAL_SURFACE('',#964,39.84);
#966=ORIENTED_EDGE('',*,*,#367,.F.);
#967=EDGE_LOOP('',(#966));
#968=FACE_BOUND('',#967,.T.);
#969=ORIENTED_EDGE('',*,*,#933,.F.);
#970=EDGE_LOOP('',(#969));
#971=FACE_BOUND('',#970,.T.);
#972=ADVANCED_FACE('F158',(#968,#971),#965,.F.);
#973=CARTESIAN_POINT('',(-6.63333333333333,0.,0.));
#974=DIRECTION('',(0.,0.,-1.));
#975=DIRECTION('',(0.,-1.,0.));
#976=AXIS2_PLACEMENT_3D('',#973,#974,#975);
#977=PLANE('',#976);
#978=CARTESIAN_POINT('',(0.,0.,-5.6843418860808E-11));
#979=DIRECTION('',(0.,0.,-1.));
#980=DIRECTION('',(0.,-1.,0.));
#981=AXIS2_PLACEMENT_3D('',#978,#979,#980);
#982=CIRCLE('',#981,4.26666666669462);
#983=CARTESIAN_POINT('',(0.,-4.26666666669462,-5.6843418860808E-11));
#984=VERTEX_POINT('',#983);
#985=EDGE_CURVE('E601',#984,#984,#982,.F.);
#986=ORIENTED_EDGE('',*,*,#985,.T.);
#987=EDGE_LOOP('',(#986));
#988=FACE_BOUND('',#987,.T.);
#989=ORIENTED_EDGE('',*,*,#956,.F.);
#990=EDGE_LOOP('',(#989));
#991=FACE_BOUND('',#990,.T.);
#992=ADVANCED_FACE('F160',(#988,#991),#977,.T.);
#993=CARTESIAN_POINT('',(0.,0.,-5.6843418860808E-11));
#994=DIRECTION('',(0.,0.,-1.));
#995=DIRECTION('',(0.,-1.,0.));
#996=AXIS2_PLACEMENT_3D('',#993,#994,#995);
#997=CONICAL_SURFACE('',#996,4.26666666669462,0.785398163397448);
#998=ORIENTED_EDGE('',*,*,#985,.F.);
#999=EDGE_LOOP('',(#998));
#1000=FACE_BOUND('',#999,.T.);
#1001=CARTESIAN_POINT('',(0.,0.,0.266666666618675));
#1002=DIRECTION('',(0.,0.,-1.));
#1003=DIRECTION('',(-1.,0.,0.));
#1004=AXIS2_PLACEMENT_3D('',#1001,#1002,#1003);
#1005=CIRCLE('',#1004,4.0000000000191);
#1006=CARTESIAN_POINT('',(-4.0000000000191,0.,0.266666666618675));
#1007=VERTEX_POINT('',#1006);
#1008=EDGE_CURVE('E604',#1007,#1007,#1005,.T.);
#1009=ORIENTED_EDGE('',*,*,#1008,.F.);
#1010=EDGE_LOOP('',(#1009));
#1011=FACE_BOUND('',#1010,.T.);
#1012=ADVANCED_FACE('F163',(#1000,#1011),#997,.F.);
#1013=CARTESIAN_POINT('',(0.,0.,8.5));
#1014=DIRECTION('',(0.,0.,-1.));
#1015=DIRECTION('',(0.,-1.,0.));
#1016=AXIS2_PLACEMENT_3D('',#1013,#1014,#1015);
#1017=CYLINDRICAL_SURFACE('',#1016,4.);
#1018=ORIENTED_EDGE('',*,*,#1008,.T.);
#1019=EDGE_LOOP('',(#1018));
#1020=FACE_BOUND('',#1019,.T.);
#1021=CARTESIAN_POINT('',(0.,0.,16.7333333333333));
#1022=DIRECTION('',(0.,0.,-1.));
#1023=DIRECTION('',(0.,-1.,0.));
#1024=AXIS2_PLACEMENT_3D('',#1021,#1022,#1023);
#1025=CIRCLE('',#1024,4.);
#1026=CARTESIAN_POINT('',(0.,-4.,16.7333333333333));
#1027=VERTEX_POINT('',#1026);
#1028=EDGE_CURVE('E608',#1027,#1027,#1025,.T.);
#1029=ORIENTED_EDGE('',*,*,#1028,.F.);
#1030=EDGE_LOOP('',(#1029));
#1031=FACE_BOUND('',#1030,.T.);
#1032=ADVANCED_FACE('F167',(#1020,#1031),#1017,.F.);
#1033=CARTESIAN_POINT('',(0.,0.,17.0000000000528));
#1034=DIRECTION('',(0.,0.,1.));
#1035=DIRECTION('',(0.,1.,0.));
#1036=AXIS2_PLACEMENT_3D('',#1033,#1034,#1035);
#1037=CONICAL_SURFACE('',#1036,4.26666666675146,0.78539816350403);
#1038=ORIENTED_EDGE('',*,*,#1028,.T.);
#1039=EDGE_LOOP('',(#1038));
#1040=FACE_BOUND('',#1039,.T.);
#1041=CARTESIAN_POINT('',(0.,0.,16.999999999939));
#1042=DIRECTION('',(0.,0.,1.));
#1043=DIRECTION('',(0.,1.,0.));
#1044=AXIS2_PLACEMENT_3D('',#1041,#1042,#1043);
#1045=CIRCLE('',#1044,4.26666666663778);
#1046=CARTESIAN_POINT('',(0.,4.26666666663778,16.999999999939));
#1047=VERTEX_POINT('',#1046);
#1048=EDGE_CURVE('E605',#1047,#1047,#1045,.F.);
#1049=ORIENTED_EDGE('',*,*,#1048,.F.);
#1050=EDGE_LOOP('',(#1049));
#1051=FACE_BOUND('',#1050,.T.);
#1052=ADVANCED_FACE('F171',(#1040,#1051),#1037,.F.);
#1053=CARTESIAN_POINT('',(-6.13333333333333,0.,17.));
#1054=DIRECTION('',(0.,0.,1.));
#1055=DIRECTION('',(0.,1.,0.));
#1056=AXIS2_PLACEMENT_3D('',#1053,#1054,#1055);
#1057=PLANE('',#1056);
#1058=CARTESIAN_POINT('',(0.,0.,17.));
#1059=DIRECTION('',(0.,0.,-1.));
#1060=DIRECTION('',(0.,-1.,0.));
#1061=AXIS2_PLACEMENT_3D('',#1058,#1059,#1060);
#1062=CIRCLE('',#1061,8.);
#1063=CARTESIAN_POINT('',(0.,-8.,17.));
#1064=VERTEX_POINT('',#1063);
#1065=EDGE_CURVE('E609',#1064,#1064,#1062,.F.);
#1066=ORIENTED_EDGE('',*,*,#1065,.T.);
#1067=EDGE_LOOP('',(#1066));
#1068=FACE_BOUND('',#1067,.T.);
#1069=ORIENTED_EDGE('',*,*,#1048,.T.);
#1070=EDGE_LOOP('',(#1069));
#1071=FACE_BOUND('',#1070,.T.);
#1072=ADVANCED_FACE('F175',(#1068,#1071),#1057,.T.);
#1073=CARTESIAN_POINT('',(0.,0.,17.85));
#1074=DIRECTION('',(0.,0.,-1.));
#1075=DIRECTION('',(0.,-1.,0.));
#1076=AXIS2_PLACEMENT_3D('',#1073,#1074,#1075);
#1077=CYLINDRICAL_SURFACE('',#1076,8.);
#1078=ORIENTED_EDGE('',*,*,#1065,.F.);
#1079=EDGE_LOOP('',(#1078));
#1080=FACE_BOUND('',#1079,.T.);
#1081=CARTESIAN_POINT('',(0.,0.,18.7));
#1082=DIRECTION('',(0.,0.,-1.));
#1083=DIRECTION('',(0.,-1.,0.));
#1084=AXIS2_PLACEMENT_3D('',#1081,#1082,#1083);
#1085=CIRCLE('',#1084,8.);
#1086=CARTESIAN_POINT('',(0.,-8.,18.7));
#1087=VERTEX_POINT('',#1086);
#1088=EDGE_CURVE('E612',#1087,#1087,#1085,.T.);
#1089=ORIENTED_EDGE('',*,*,#1088,.F.);
#1090=EDGE_LOOP('',(#1089));
#1091=FACE_BOUND('',#1090,.T.);
#1092=ADVANCED_FACE('F178',(#1080,#1091),#1077,.F.);
#1093=CARTESIAN_POINT('',(-4.,0.,18.7));
#1094=DIRECTION('',(0.,0.,-1.));
#1095=DIRECTION('',(0.,-1.,0.));
#1096=AXIS2_PLACEMENT_3D('',#1093,#1094,#1095);
#1097=PLANE('',#1096);
#1098=ORIENTED_EDGE('',*,*,#1088,.T.);
#1099=EDGE_LOOP('',(#1098));
#1100=FACE_BOUND('',#1099,.T.);
#1101=ADVANCED_FACE('F17',(#1100),#1097,.T.);
#1102=CARTESIAN_POINT('',(30.5,-1.19325,16.));
#1103=DIRECTION('',(0.,0.,-1.));
#1104=DIRECTION('',(0.,-1.,0.));
#1105=AXIS2_PLACEMENT_3D('',#1102,#1103,#1104);
#1106=PLANE('',#1105);
#1107=CARTESIAN_POINT('',(30.5,0.,16.0000000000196));
#1108=DIRECTION('',(0.,0.,1.));
#1109=DIRECTION('',(0.,1.,0.));
#1110=AXIS2_PLACEMENT_3D('',#1107,#1108,#1109);
#1111=CIRCLE('',#1110,2.38650000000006);
#1112=CARTESIAN_POINT('',(30.5,2.38650000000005,16.0000000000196));
#1113=VERTEX_POINT('',#1112);
#1114=EDGE_CURVE('E236',#1113,#1113,#1111,.T.);
#1115=ORIENTED_EDGE('',*,*,#1114,.F.);
#1116=EDGE_LOOP('',(#1115));
#1117=FACE_BOUND('',#1116,.T.);
#1118=DIRECTION('',(0.,-1.,0.));
#1119=VECTOR('',#1118,1.);
#1120=CARTESIAN_POINT('',(29.,-0.866025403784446,16.));
#1121=LINE('',#1120,#1119);
#1122=CARTESIAN_POINT('',(29.,0.866025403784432,16.));
#1123=VERTEX_POINT('',#1122);
#1124=CARTESIAN_POINT('',(29.,-0.866025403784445,16.));
#1125=VERTEX_POINT('',#1124);
#1126=EDGE_CURVE('E261',#1123,#1125,#1121,.T.);
#1127=ORIENTED_EDGE('',*,*,#1126,.T.);
#1128=DIRECTION('',(0.86602540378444,-0.5,0.));
#1129=VECTOR('',#1128,1.);
#1130=CARTESIAN_POINT('',(29.,-0.866025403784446,16.));
#1131=LINE('',#1130,#1129);
#1132=CARTESIAN_POINT('',(30.5,-1.73205080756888,16.));
#1133=VERTEX_POINT('',#1132);
#1134=EDGE_CURVE('E237',#1125,#1133,#1131,.T.);
#1135=ORIENTED_EDGE('',*,*,#1134,.T.);
#1136=DIRECTION('',(0.866025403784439,0.5,0.));
#1137=VECTOR('',#1136,1.);
#1138=CARTESIAN_POINT('',(32.,-0.866025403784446,16.));
#1139=LINE('',#1138,#1137);
#1140=CARTESIAN_POINT('',(32.,-0.866025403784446,16.));
#1141=VERTEX_POINT('',#1140);
#1142=EDGE_CURVE('E258',#1133,#1141,#1139,.T.);
#1143=ORIENTED_EDGE('',*,*,#1142,.T.);
#1144=DIRECTION('',(0.,1.,0.));
#1145=VECTOR('',#1144,1.);
#1146=CARTESIAN_POINT('',(32.,0.866025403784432,16.));
#1147=LINE('',#1146,#1145);
#1148=CARTESIAN_POINT('',(32.,0.866025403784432,16.));
#1149=VERTEX_POINT('',#1148);
#1150=EDGE_CURVE('E273',#1141,#1149,#1147,.T.);
#1151=ORIENTED_EDGE('',*,*,#1150,.T.);
#1152=DIRECTION('',(-0.866025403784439,0.5,0.));
#1153=VECTOR('',#1152,1.);
#1154=CARTESIAN_POINT('',(30.5,1.73205080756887,16.));
#1155=LINE('',#1154,#1153);
#1156=CARTESIAN_POINT('',(30.5,1.73205080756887,16.));
#1157=VERTEX_POINT('',#1156);
#1158=EDGE_CURVE('E288',#1149,#1157,#1155,.T.);
#1159=ORIENTED_EDGE('',*,*,#1158,.T.);
#1160=DIRECTION('',(-0.866025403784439,-0.5,0.));
#1161=VECTOR('',#1160,1.);
#1162=CARTESIAN_POINT('',(29.,0.866025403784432,16.));
#1163=LINE('',#1162,#1161);
#1164=EDGE_CURVE('E279',#1157,#1123,#1163,.T.);
#1165=ORIENTED_EDGE('',*,*,#1164,.T.);
#1166=EDGE_LOOP('',(#1127,#1135,#1143,#1151,#1159,#1165));
#1167=FACE_BOUND('',#1166,.T.);
#1168=ADVANCED_FACE('F187',(#1117,#1167),#1106,.T.);
#1169=CARTESIAN_POINT('',(30.5,-1.73205080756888,16.));
#1170=DIRECTION('',(-0.5,-0.866025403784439,0.));
#1171=DIRECTION('',(0.866025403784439,-0.5,0.));
#1172=AXIS2_PLACEMENT_3D('',#1169,#1170,#1171);
#1173=PLANE('',#1172);
#1174=DIRECTION('',(0.,0.,1.));
#1175=VECTOR('',#1174,1.);
#1176=CARTESIAN_POINT('',(30.5,-1.73205080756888,16.));
#1177=LINE('',#1176,#1175);
#1178=CARTESIAN_POINT('',(30.5,-1.73205080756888,19.));
#1179=VERTEX_POINT('',#1178);
#1180=EDGE_CURVE('E243',#1133,#1179,#1177,.T.);
#1181=ORIENTED_EDGE('',*,*,#1180,.F.);
#1182=ORIENTED_EDGE('',*,*,#1134,.F.);
#1183=DIRECTION('',(0.,0.,1.));
#1184=VECTOR('',#1183,1.);
#1185=CARTESIAN_POINT('',(29.,-0.866025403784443,16.));
#1186=LINE('',#1185,#1184);
#1187=CARTESIAN_POINT('',(29.,-0.866025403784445,19.));
#1188=VERTEX_POINT('',#1187);
#1189=EDGE_CURVE('E246',#1188,#1125,#1186,.F.);
#1190=ORIENTED_EDGE('',*,*,#1189,.F.);
#1191=DIRECTION('',(0.866025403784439,-0.5,0.));
#1192=VECTOR('',#1191,1.);
#1193=CARTESIAN_POINT('',(30.5,-1.73205080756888,19.));
#1194=LINE('',#1193,#1192);
#1195=EDGE_CURVE('E240',#1179,#1188,#1194,.F.);
#1196=ORIENTED_EDGE('',*,*,#1195,.F.);
#1197=EDGE_LOOP('',(#1181,#1182,#1190,#1196));
#1198=FACE_BOUND('',#1197,.T.);
#1199=ADVANCED_FACE('F725',(#1198),#1173,.F.);
#1200=CARTESIAN_POINT('',(30.5,0.,19.));
#1201=DIRECTION('',(0.,0.,1.));
#1202=DIRECTION('',(0.,1.,0.));
#1203=AXIS2_PLACEMENT_3D('',#1200,#1201,#1202);
#1204=PLANE('',#1203);
#1205=ORIENTED_EDGE('',*,*,#1195,.T.);
#1206=DIRECTION('',(0.,1.,0.));
#1207=VECTOR('',#1206,1.);
#1208=CARTESIAN_POINT('',(29.,0.,19.));
#1209=LINE('',#1208,#1207);
#1210=CARTESIAN_POINT('',(29.,0.866025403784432,19.));
#1211=VERTEX_POINT('',#1210);
#1212=EDGE_CURVE('E252',#1211,#1188,#1209,.F.);
#1213=ORIENTED_EDGE('',*,*,#1212,.F.);
#1214=DIRECTION('',(-0.866025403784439,-0.5,0.));
#1215=VECTOR('',#1214,1.);
#1216=CARTESIAN_POINT('',(29.,0.866025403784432,19.));
#1217=LINE('',#1216,#1215);
#1218=CARTESIAN_POINT('',(30.5,1.73205080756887,19.));
#1219=VERTEX_POINT('',#1218);
#1220=EDGE_CURVE('E276',#1211,#1219,#1217,.F.);
#1221=ORIENTED_EDGE('',*,*,#1220,.T.);
#1222=DIRECTION('',(-0.866025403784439,0.5,0.));
#1223=VECTOR('',#1222,1.);
#1224=CARTESIAN_POINT('',(30.5,1.73205080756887,19.));
#1225=LINE('',#1224,#1223);
#1226=CARTESIAN_POINT('',(32.,0.866025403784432,19.));
#1227=VERTEX_POINT('',#1226);
#1228=EDGE_CURVE('E285',#1219,#1227,#1225,.F.);
#1229=ORIENTED_EDGE('',*,*,#1228,.T.);
#1230=DIRECTION('',(0.,1.,0.));
#1231=VECTOR('',#1230,1.);
#1232=CARTESIAN_POINT('',(32.,0.866025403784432,19.));
#1233=LINE('',#1232,#1231);
#1234=CARTESIAN_POINT('',(32.,-0.866025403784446,19.));
#1235=VERTEX_POINT('',#1234);
#1236=EDGE_CURVE('E267',#1227,#1235,#1233,.F.);
#1237=ORIENTED_EDGE('',*,*,#1236,.T.);
#1238=DIRECTION('',(0.86602540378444,0.5,0.));
#1239=VECTOR('',#1238,1.);
#1240=CARTESIAN_POINT('',(30.5,-1.73205080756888,19.));
#1241=LINE('',#1240,#1239);
#1242=EDGE_CURVE('E249',#1179,#1235,#1241,.T.);
#1243=ORIENTED_EDGE('',*,*,#1242,.F.);
#1244=EDGE_LOOP('',(#1205,#1213,#1221,#1229,#1237,#1243));
#1245=FACE_BOUND('',#1244,.T.);
#1246=ADVANCED_FACE('F729',(#1245),#1204,.F.);
#1247=CARTESIAN_POINT('',(32.,-0.866025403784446,16.));
#1248=DIRECTION('',(0.5,-0.866025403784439,0.));
#1249=DIRECTION('',(0.866025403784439,0.5,0.));
#1250=AXIS2_PLACEMENT_3D('',#1247,#1248,#1249);
#1251=PLANE('',#1250);
#1252=DIRECTION('',(0.,0.,1.));
#1253=VECTOR('',#1252,1.);
#1254=CARTESIAN_POINT('',(32.,-0.866025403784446,16.));
#1255=LINE('',#1254,#1253);
#1256=EDGE_CURVE('E255',#1141,#1235,#1255,.T.);
#1257=ORIENTED_EDGE('',*,*,#1256,.F.);
#1258=ORIENTED_EDGE('',*,*,#1142,.F.);
#1259=ORIENTED_EDGE('',*,*,#1180,.T.);
#1260=ORIENTED_EDGE('',*,*,#1242,.T.);
#1261=EDGE_LOOP('',(#1257,#1258,#1259,#1260));
#1262=FACE_BOUND('',#1261,.T.);
#1263=ADVANCED_FACE('F733',(#1262),#1251,.F.);
#1264=CARTESIAN_POINT('',(29.,-0.866025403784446,16.));
#1265=DIRECTION('',(-1.,0.,0.));
#1266=DIRECTION('',(0.,-1.,0.));
#1267=AXIS2_PLACEMENT_3D('',#1264,#1265,#1266);
#1268=PLANE('',#1267);
#1269=ORIENTED_EDGE('',*,*,#1189,.T.);
#1270=ORIENTED_EDGE('',*,*,#1126,.F.);
#1271=DIRECTION('',(0.,0.,1.));
#1272=VECTOR('',#1271,1.);
#1273=CARTESIAN_POINT('',(29.,0.866025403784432,16.));
#1274=LINE('',#1273,#1272);
#1275=EDGE_CURVE('E264',#1211,#1123,#1274,.F.);
#1276=ORIENTED_EDGE('',*,*,#1275,.F.);
#1277=ORIENTED_EDGE('',*,*,#1212,.T.);
#1278=EDGE_LOOP('',(#1269,#1270,#1276,#1277));
#1279=FACE_BOUND('',#1278,.T.);
#1280=ADVANCED_FACE('F737',(#1279),#1268,.F.);
#1281=CARTESIAN_POINT('',(32.,0.866025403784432,16.));
#1282=DIRECTION('',(1.,0.,0.));
#1283=DIRECTION('',(0.,1.,0.));
#1284=AXIS2_PLACEMENT_3D('',#1281,#1282,#1283);
#1285=PLANE('',#1284);
#1286=DIRECTION('',(0.,0.,1.));
#1287=VECTOR('',#1286,1.);
#1288=CARTESIAN_POINT('',(32.,0.866025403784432,16.));
#1289=LINE('',#1288,#1287);
#1290=EDGE_CURVE('E270',#1149,#1227,#1289,.T.);
#1291=ORIENTED_EDGE('',*,*,#1290,.F.);
#1292=ORIENTED_EDGE('',*,*,#1150,.F.);
#1293=ORIENTED_EDGE('',*,*,#1256,.T.);
#1294=ORIENTED_EDGE('',*,*,#1236,.F.);
#1295=EDGE_LOOP('',(#1291,#1292,#1293,#1294));
#1296=FACE_BOUND('',#1295,.T.);
#1297=ADVANCED_FACE('F741',(#1296),#1285,.F.);
#1298=CARTESIAN_POINT('',(29.,0.866025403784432,16.));
#1299=DIRECTION('',(-0.5,0.866025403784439,0.));
#1300=DIRECTION('',(-0.866025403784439,-0.5,0.));
#1301=AXIS2_PLACEMENT_3D('',#1298,#1299,#1300);
#1302=PLANE('',#1301);
#1303=ORIENTED_EDGE('',*,*,#1275,.T.);
#1304=ORIENTED_EDGE('',*,*,#1164,.F.);
#1305=DIRECTION('',(0.,0.,1.));
#1306=VECTOR('',#1305,1.);
#1307=CARTESIAN_POINT('',(30.5,1.73205080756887,16.));
#1308=LINE('',#1307,#1306);
#1309=EDGE_CURVE('E282',#1219,#1157,#1308,.F.);
#1310=ORIENTED_EDGE('',*,*,#1309,.F.);
#1311=ORIENTED_EDGE('',*,*,#1220,.F.);
#1312=EDGE_LOOP('',(#1303,#1304,#1310,#1311));
#1313=FACE_BOUND('',#1312,.T.);
#1314=ADVANCED_FACE('F745',(#1313),#1302,.F.);
#1315=CARTESIAN_POINT('',(30.5,1.73205080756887,16.));
#1316=DIRECTION('',(0.5,0.866025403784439,0.));
#1317=DIRECTION('',(-0.866025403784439,0.5,0.));
#1318=AXIS2_PLACEMENT_3D('',#1315,#1316,#1317);
#1319=PLANE('',#1318);
#1320=ORIENTED_EDGE('',*,*,#1309,.T.);
#1321=ORIENTED_EDGE('',*,*,#1158,.F.);
#1322=ORIENTED_EDGE('',*,*,#1290,.T.);
#1323=ORIENTED_EDGE('',*,*,#1228,.F.);
#1324=EDGE_LOOP('',(#1320,#1321,#1322,#1323));
#1325=FACE_BOUND('',#1324,.T.);
#1326=ADVANCED_FACE('F749',(#1325),#1319,.F.);
#1327=CARTESIAN_POINT('',(30.5,0.,21.85));
#1328=DIRECTION('',(0.,0.,1.));
#1329=DIRECTION('',(0.,1.,0.));
#1330=AXIS2_PLACEMENT_3D('',#1327,#1328,#1329);
#1331=CYLINDRICAL_SURFACE('',#1330,3.);
#1332=CARTESIAN_POINT('',(30.5,0.,16.6135));
#1333=DIRECTION('',(0.,0.,1.));
#1334=DIRECTION('',(0.,1.,0.));
#1335=AXIS2_PLACEMENT_3D('',#1332,#1333,#1334);
#1336=CIRCLE('',#1335,3.);
#1337=EDGE_CURVE('E233',#542,#420,#1336,.T.);
#1338=ORIENTED_EDGE('',*,*,#1337,.T.);
#1339=ORIENTED_EDGE('',*,*,#566,.T.);
#1340=ORIENTED_EDGE('',*,*,#763,.T.);
#1341=ORIENTED_EDGE('',*,*,#551,.T.);
#1342=EDGE_LOOP('',(#1338,#1339,#1340,#1341));
#1343=FACE_BOUND('',#1342,.T.);
#1344=ADVANCED_FACE('F323',(#1343),#1331,.T.);
#1345=CARTESIAN_POINT('',(30.5,0.,16.6135000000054));
#1346=DIRECTION('',(0.,0.,1.));
#1347=DIRECTION('',(0.,1.,0.));
#1348=AXIS2_PLACEMENT_3D('',#1345,#1346,#1347);
#1349=CONICAL_SURFACE('',#1348,2.99999999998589,0.785398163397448);
#1350=ORIENTED_EDGE('',*,*,#1114,.T.);
#1351=EDGE_LOOP('',(#1350));
#1352=FACE_BOUND('',#1351,.T.);
#1353=ORIENTED_EDGE('',*,*,#581,.T.);
#1354=ORIENTED_EDGE('',*,*,#421,.T.);
#1355=ORIENTED_EDGE('',*,*,#1337,.F.);
#1356=ORIENTED_EDGE('',*,*,#543,.T.);
#1357=EDGE_LOOP('',(#1353,#1354,#1355,#1356));
#1358=FACE_BOUND('',#1357,.T.);
#1359=ADVANCED_FACE('F718',(#1352,#1358),#1349,.T.);
#1360=CARTESIAN_POINT('',(30.5,0.,29.15));
#1361=DIRECTION('',(0.,0.,1.));
#1362=DIRECTION('',(0.,1.,0.));
#1363=AXIS2_PLACEMENT_3D('',#1360,#1361,#1362);
#1364=CYLINDRICAL_SURFACE('',#1363,4.875);
#1365=ORIENTED_EDGE('',*,*,#31,.T.);
#1366=EDGE_LOOP('',(#1365));
#1367=FACE_BOUND('',#1366,.T.);
#1368=CARTESIAN_POINT('',(30.5,0.,29.3));
#1369=DIRECTION('',(0.,0.,1.));
#1370=DIRECTION('',(0.,1.,0.));
#1371=AXIS2_PLACEMENT_3D('',#1368,#1369,#1370);
#1372=CIRCLE('',#1371,4.875);
#1373=CARTESIAN_POINT('',(30.5,4.87499999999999,29.3));
#1374=VERTEX_POINT('',#1373);
#1375=EDGE_CURVE('E294',#1374,#1374,#1372,.T.);
#1376=ORIENTED_EDGE('',*,*,#1375,.F.);
#1377=EDGE_LOOP('',(#1376));
#1378=FACE_BOUND('',#1377,.T.);
#1379=ADVANCED_FACE('F189',(#1367,#1378),#1364,.T.);
#1380=CARTESIAN_POINT('',(30.5,-5.6875,29.3));
#1381=DIRECTION('',(0.,0.,-1.));
#1382=DIRECTION('',(0.,-1.,0.));
#1383=AXIS2_PLACEMENT_3D('',#1380,#1381,#1382);
#1384=PLANE('',#1383);
#1385=CARTESIAN_POINT('',(30.5,0.,29.3));
#1386=DIRECTION('',(0.,0.,1.));
#1387=DIRECTION('',(0.,1.,0.));
#1388=AXIS2_PLACEMENT_3D('',#1385,#1386,#1387);
#1389=CIRCLE('',#1388,6.5);
#1390=CARTESIAN_POINT('',(30.5,6.49999999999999,29.3));
#1391=VERTEX_POINT('',#1390);
#1392=EDGE_CURVE('E225',#1391,#1391,#1389,.T.);
#1393=ORIENTED_EDGE('',*,*,#1392,.F.);
#1394=EDGE_LOOP('',(#1393));
#1395=FACE_BOUND('',#1394,.T.);
#1396=ORIENTED_EDGE('',*,*,#1375,.T.);
#1397=EDGE_LOOP('',(#1396));
#1398=FACE_BOUND('',#1397,.T.);
#1399=ADVANCED_FACE('F875',(#1395,#1398),#1384,.T.);
#1400=CARTESIAN_POINT('',(30.5,0.,36.65));
#1401=DIRECTION('',(0.,0.,1.));
#1402=DIRECTION('',(0.,1.,0.));
#1403=AXIS2_PLACEMENT_3D('',#1400,#1401,#1402);
#1404=CYLINDRICAL_SURFACE('',#1403,6.5);
#1405=ORIENTED_EDGE('',*,*,#1392,.T.);
#1406=EDGE_LOOP('',(#1405));
#1407=FACE_BOUND('',#1406,.T.);
#1408=CARTESIAN_POINT('',(30.5,0.,44.));
#1409=DIRECTION('',(0.,0.,-1.));
#1410=DIRECTION('',(1.,0.,0.));
#1411=AXIS2_PLACEMENT_3D('',#1408,#1409,#1410);
#1412=CIRCLE('',#1411,6.5);
#1413=CARTESIAN_POINT('',(37.,0.,44.));
#1414=VERTEX_POINT('',#1413);
#1415=EDGE_CURVE('E220',#1414,#1414,#1412,.F.);
#1416=ORIENTED_EDGE('',*,*,#1415,.F.);
#1417=EDGE_LOOP('',(#1416));
#1418=FACE_BOUND('',#1417,.T.);
#1419=ADVANCED_FACE('F211',(#1407,#1418),#1404,.T.);
#1420=CARTESIAN_POINT('',(30.5,0.,45.25));
#1421=DIRECTION('',(0.,0.,-1.));
#1422=DIRECTION('',(1.,0.,0.));
#1423=AXIS2_PLACEMENT_3D('',#1420,#1421,#1422);
#1424=TOROIDAL_SURFACE('',#1423,6.5,1.25);
#1425=CARTESIAN_POINT('',(30.5,0.,45.25));
#1426=DIRECTION('',(0.,0.,1.));
#1427=DIRECTION('',(0.,1.,0.));
#1428=AXIS2_PLACEMENT_3D('',#1425,#1426,#1427);
#1429=CIRCLE('',#1428,7.75);
#1430=CARTESIAN_POINT('',(30.5,7.74999999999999,45.25));
#1431=VERTEX_POINT('',#1430);
#1432=EDGE_CURVE('E219',#1431,#1431,#1429,.T.);
#1433=ORIENTED_EDGE('',*,*,#1432,.F.);
#1434=EDGE_LOOP('',(#1433));
#1435=FACE_BOUND('',#1434,.T.);
#1436=ORIENTED_EDGE('',*,*,#1415,.T.);
#1437=EDGE_LOOP('',(#1436));
#1438=FACE_BOUND('',#1437,.T.);
#1439=ADVANCED_FACE('F202',(#1435,#1438),#1424,.T.);
#1440=CARTESIAN_POINT('',(30.5,0.,55.75));
#1441=DIRECTION('',(0.,0.,1.));
#1442=DIRECTION('',(0.,1.,0.));
#1443=AXIS2_PLACEMENT_3D('',#1440,#1441,#1442);
#1444=CYLINDRICAL_SURFACE('',#1443,7.75);
#1445=CARTESIAN_POINT('',(30.5,0.,66.25));
#1446=DIRECTION('',(0.,0.,1.));
#1447=DIRECTION('',(0.,1.,0.));
#1448=AXIS2_PLACEMENT_3D('',#1445,#1446,#1447);
#1449=CIRCLE('',#1448,7.75);
#1450=CARTESIAN_POINT('',(30.5,7.74999999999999,66.25));
#1451=VERTEX_POINT('',#1450);
#1452=EDGE_CURVE('E216',#1451,#1451,#1449,.F.);
#1453=ORIENTED_EDGE('',*,*,#1452,.T.);
#1454=EDGE_LOOP('',(#1453));
#1455=FACE_BOUND('',#1454,.T.);
#1456=ORIENTED_EDGE('',*,*,#1432,.T.);
#1457=EDGE_LOOP('',(#1456));
#1458=FACE_BOUND('',#1457,.T.);
#1459=ADVANCED_FACE('F194',(#1455,#1458),#1444,.T.);
#1460=CARTESIAN_POINT('',(30.5,0.,66.25));
#1461=DIRECTION('',(0.,0.,1.));
#1462=DIRECTION('',(0.,-1.,0.));
#1463=AXIS2_PLACEMENT_3D('',#1460,#1461,#1462);
#1464=SPHERICAL_SURFACE('',#1463,7.75);
#1465=CARTESIAN_POINT('',(30.5,0.,74.));
#1466=VERTEX_POINT('',#1465);
#1467=VERTEX_LOOP('',#1466);
#1468=FACE_BOUND('',#1467,.T.);
#1469=ORIENTED_EDGE('',*,*,#1452,.F.);
#1470=EDGE_LOOP('',(#1469));
#1471=FACE_BOUND('',#1470,.T.);
#1472=ADVANCED_FACE('F192',(#1468,#1471),#1464,.T.);
#1473=CLOSED_SHELL('',(#46,#216,#247,#267,#287,#307,#316,#354,#376,#570,#594,#612,#630,#678,
#696,#779,#799,#820,#840,#860,#880,#900,#920,#940,#960,#972,#992,#1012,#1032,#1052,#1072,#1092,
#1101,#1168,#1199,#1246,#1263,#1280,#1297,#1314,#1326,#1344,#1359,#1379,#1399,#1419,#1439,#1459,#1472));
#1474=CARTESIAN_POINT('',(30.5,0.,28.35));
#1475=DIRECTION('',(0.,0.,1.));
#1476=DIRECTION('',(0.,1.,0.));
#1477=AXIS2_PLACEMENT_3D('',#1474,#1475,#1476);
#1478=CYLINDRICAL_SURFACE('',#1477,2.3865);
#1479=CARTESIAN_POINT('',(30.5,0.,27.7));
#1480=DIRECTION('',(0.,0.,1.));
#1481=DIRECTION('',(0.,1.,0.));
#1482=AXIS2_PLACEMENT_3D('',#1479,#1480,#1481);
#1483=CIRCLE('',#1482,2.3865);
#1484=CARTESIAN_POINT('',(30.5,2.38649999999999,27.7));
#1485=VERTEX_POINT('',#1484);
#1486=EDGE_CURVE('E229',#1485,#1485,#1483,.T.);
#1487=ORIENTED_EDGE('',*,*,#1486,.T.);
#1488=EDGE_LOOP('',(#1487));
#1489=FACE_BOUND('',#1488,.T.);
#1490=CARTESIAN_POINT('',(30.5,0.,29.));
#1491=DIRECTION('',(0.,0.,1.));
#1492=DIRECTION('',(0.,1.,0.));
#1493=AXIS2_PLACEMENT_3D('',#1490,#1491,#1492);
#1494=CIRCLE('',#1493,2.3865);
#1495=CARTESIAN_POINT('',(30.5,2.38649999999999,29.));
#1496=VERTEX_POINT('',#1495);
#1497=EDGE_CURVE('E232',#1496,#1496,#1494,.T.);
#1498=ORIENTED_EDGE('',*,*,#1497,.F.);
#1499=EDGE_LOOP('',(#1498));
#1500=FACE_BOUND('',#1499,.T.);
#1501=ADVANCED_FACE('F900',(#1489,#1500),#1478,.T.);
#1502=CARTESIAN_POINT('',(30.5,-3.63075,29.));
#1503=DIRECTION('',(0.,0.,-1.));
#1504=DIRECTION('',(0.,-1.,0.));
#1505=AXIS2_PLACEMENT_3D('',#1502,#1503,#1504);
#1506=PLANE('',#1505);
#1507=ORIENTED_EDGE('',*,*,#1497,.T.);
#1508=EDGE_LOOP('',(#1507));
#1509=FACE_BOUND('',#1508,.T.);
#1510=CARTESIAN_POINT('',(30.5,0.,29.));
#1511=DIRECTION('',(0.,0.,-1.));
#1512=DIRECTION('',(0.,-1.,0.));
#1513=AXIS2_PLACEMENT_3D('',#1510,#1511,#1512);
#1514=CIRCLE('',#1513,2.99999999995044);
#1515=CARTESIAN_POINT('',(30.5,-2.99999999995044,29.));
#1516=VERTEX_POINT('',#1515);
#1517=EDGE_CURVE('E228',#1516,#1516,#1514,.T.);
#1518=ORIENTED_EDGE('',*,*,#1517,.T.);
#1519=EDGE_LOOP('',(#1518));
#1520=FACE_BOUND('',#1519,.T.);
#1521=ADVANCED_FACE('F903',(#1509,#1520),#1506,.T.);
#1522=CARTESIAN_POINT('',(30.5,0.,27.086499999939));
#1523=DIRECTION('',(0.,0.,-1.));
#1524=DIRECTION('',(0.,-1.,0.));
#1525=AXIS2_PLACEMENT_3D('',#1522,#1523,#1524);
#1526=CONICAL_SURFACE('',#1525,2.99999999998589,0.785398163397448);
#1527=ORIENTED_EDGE('',*,*,#1486,.F.);
#1528=EDGE_LOOP('',(#1527));
#1529=FACE_BOUND('',#1528,.T.);
#1530=CARTESIAN_POINT('',(30.5,0.,27.6279999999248));
#1531=DIRECTION('',(0.,0.,-1.));
#1532=DIRECTION('',(0.,-1.,0.));
#1533=AXIS2_PLACEMENT_3D('',#1530,#1531,#1532);
#1534=CIRCLE('',#1533,2.4585);
#1535=CARTESIAN_POINT('',(30.5,-2.45850000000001,27.6279999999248));
#1536=VERTEX_POINT('',#1535);
#1537=EDGE_CURVE('E306',#1536,#1536,#1534,.F.);
#1538=ORIENTED_EDGE('',*,*,#1537,.T.);
#1539=EDGE_LOOP('',(#1538));
#1540=FACE_BOUND('',#1539,.T.);
#1541=ADVANCED_FACE('F914',(#1529,#1540),#1526,.T.);
#1542=ORIENTED_EDGE('',*,*,#1537,.F.);
#1543=EDGE_LOOP('',(#1542));
#1544=FACE_BOUND('',#1543,.T.);
#1545=CARTESIAN_POINT('',(30.5,0.,28.4584999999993));
#1546=DIRECTION('',(0.,0.,1.));
#1547=DIRECTION('',(1.,0.,0.));
#1548=AXIS2_PLACEMENT_3D('',#1545,#1546,#1547);
#1549=CIRCLE('',#1548,2.45849999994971);
#1550=CARTESIAN_POINT('',(32.9584999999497,0.,28.4584999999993));
#1551=VERTEX_POINT('',#1550);
#1552=EDGE_CURVE('E689',#1551,#1551,#1549,.T.);
#1553=ORIENTED_EDGE('',*,*,#1552,.T.);
#1554=EDGE_LOOP('',(#1553));
#1555=FACE_BOUND('',#1554,.T.);
#1556=ADVANCED_FACE('F547',(#1544,#1555),#575,.F.);
#1557=CARTESIAN_POINT('',(30.5,0.,29.0000000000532));
#1558=DIRECTION('',(0.,0.,1.));
#1559=DIRECTION('',(0.,1.,0.));
#1560=AXIS2_PLACEMENT_3D('',#1557,#1558,#1559);
#1561=CONICAL_SURFACE('',#1560,3.00000000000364,0.785398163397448);
#1562=ORIENTED_EDGE('',*,*,#1517,.F.);
#1563=EDGE_LOOP('',(#1562));
#1564=FACE_BOUND('',#1563,.T.);
#1565=ORIENTED_EDGE('',*,*,#1552,.F.);
#1566=EDGE_LOOP('',(#1565));
#1567=FACE_BOUND('',#1566,.T.);
#1568=ADVANCED_FACE('F640',(#1564,#1567),#1561,.F.);
#1569=CLOSED_SHELL('',(#1501,#1521,#1541,#1556,#1568));
#1570=ORIENTED_CLOSED_SHELL('',*,#1569,.T.);
#1571=BREP_WITH_VOIDS('B1',#1473,(#1570));
#1572=ADVANCED_BREP_SHAPE_REPRESENTATION('',(#18,#1571),#14);
#1573=SHAPE_DEFINITION_REPRESENTATION(#9,#1572);
ENDSEC;
END-ISO-10303-21;
